# Created by MC2 : Version 2012.02.00.d on 2025/04/08, 10:16:32

###############################################################################
#        Software       : TSMC MEMORY COMPILER 2012.02.00.d
#        Technology     : 28 nm CMOS LOGIC High Performance Compact Mobile Computing Plus 1P10M HKMG CU_ELK 0.9V
#        Memory Type    : TSMC 28nm High Performance Compact Mobile Computing Plus Two Port Register File
#                       : with d240 bit cell HVT periphery
#        Library Name   : ts6n28hpcphvta64x8m4fwbso
#        Library Version: 200b
#        Generated Time : 2025/04/08, 10:16:27
###############################################################################
#
#STATEMENT OF USE
#
#This information contains confidential and proprietary information of TSMC.
#No part of this information may be reproduced, transmitted, transcribed,
#stored in a retrieval system, or translated into any human or computer
#language, in any form or by any means, electronic, mechanical, magnetic,
#optical, chemical, manual, or otherwise, without the prior written permission
#of TSMC. This information was prepared for informational purpose and is for
#use by TSMC's customers only. TSMC reserves the right to make changes in the
#information at any time and without notice.
#
###############################################################################
VERSION 5.7 ;
BUSBITCHARS "[]" ;
DIVIDERCHAR "/" ;

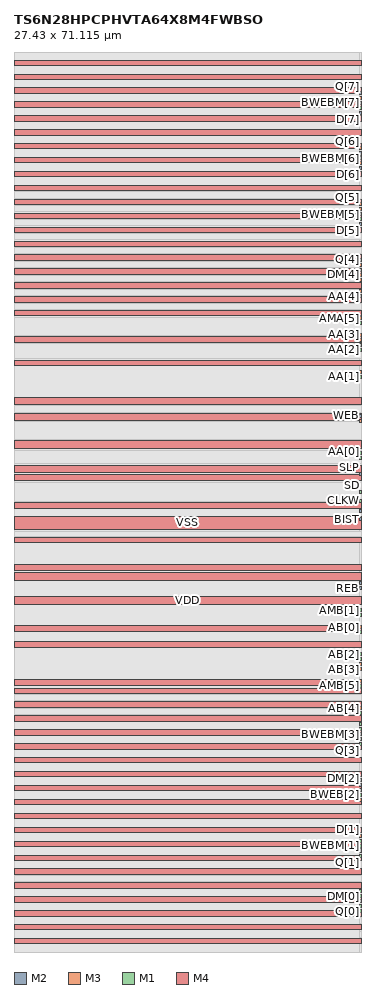
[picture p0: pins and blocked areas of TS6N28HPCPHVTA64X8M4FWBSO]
MACRO TS6N28HPCPHVTA64X8M4FWBSO
	CLASS BLOCK ;
	FOREIGN TS6N28HPCPHVTA64X8M4FWBSO 0.0 0.0 ;
	ORIGIN 0.0 0.0 ;
	SIZE 27.430 BY 71.115 ;
	SYMMETRY X Y ;
	PIN AA[0]
		DIRECTION INPUT ;
		USE SIGNAL ;
		PORT
			LAYER M2 ;
			RECT 27.280 38.930 27.430 39.170 ;
			LAYER M3 ;
			RECT 27.280 38.930 27.430 39.170 ;
			LAYER M1 ;
			RECT 27.280 38.930 27.430 39.170 ;
		END
		ANTENNAGATEAREA 0.0675 LAYER M1 ;
		ANTENNADIFFAREA 0.0360 LAYER M1 ;
		ANTENNAPARTIALMETALAREA 0.6083 LAYER M1 ;
		ANTENNAMAXAREACAR 1.9820 LAYER M1 ;
		ANTENNAPARTIALCUTAREA 0.0345 LAYER VIA1 ;
		ANTENNAMAXAREACAR 0.5856 LAYER VIA1 ;
		ANTENNAGATEAREA 0.0675 LAYER M2 ;
		ANTENNADIFFAREA 0.0360 LAYER M2 ;
		ANTENNAPARTIALMETALAREA 0.7719 LAYER M2 ;
		ANTENNAMAXAREACAR 16.5354 LAYER M2 ;
		ANTENNAPARTIALCUTAREA 0.0165 LAYER VIA2 ;
		ANTENNAMAXAREACAR 0.8398 LAYER VIA2 ;
		ANTENNAGATEAREA 0.0675 LAYER M3 ;
		ANTENNADIFFAREA 0.0360 LAYER M3 ;
		ANTENNAPARTIALMETALAREA 0.7208 LAYER M3 ;
		ANTENNAMAXAREACAR 23.7892 LAYER M3 ;
	END AA[0]

	PIN AA[1]
		DIRECTION INPUT ;
		USE SIGNAL ;
		PORT
			LAYER M3 ;
			RECT 27.280 45.320 27.430 45.560 ;
			LAYER M2 ;
			RECT 27.280 45.320 27.430 45.560 ;
			LAYER M1 ;
			RECT 27.280 45.320 27.430 45.560 ;
		END
		ANTENNAGATEAREA 0.0675 LAYER M1 ;
		ANTENNADIFFAREA 0.0360 LAYER M1 ;
		ANTENNAPARTIALMETALAREA 0.6083 LAYER M1 ;
		ANTENNAMAXAREACAR 1.9820 LAYER M1 ;
		ANTENNAPARTIALCUTAREA 0.0345 LAYER VIA1 ;
		ANTENNAMAXAREACAR 0.5856 LAYER VIA1 ;
		ANTENNAGATEAREA 0.0675 LAYER M2 ;
		ANTENNADIFFAREA 0.0360 LAYER M2 ;
		ANTENNAPARTIALMETALAREA 0.7719 LAYER M2 ;
		ANTENNAMAXAREACAR 16.5354 LAYER M2 ;
		ANTENNAPARTIALCUTAREA 0.0165 LAYER VIA2 ;
		ANTENNAMAXAREACAR 0.8398 LAYER VIA2 ;
		ANTENNAGATEAREA 0.0675 LAYER M3 ;
		ANTENNADIFFAREA 0.0360 LAYER M3 ;
		ANTENNAPARTIALMETALAREA 0.7208 LAYER M3 ;
		ANTENNAMAXAREACAR 23.7892 LAYER M3 ;
	END AA[1]

	PIN AA[2]
		DIRECTION INPUT ;
		USE SIGNAL ;
		PORT
			LAYER M3 ;
			RECT 27.280 47.450 27.430 47.690 ;
			LAYER M2 ;
			RECT 27.280 47.450 27.430 47.690 ;
			LAYER M1 ;
			RECT 27.280 47.450 27.430 47.690 ;
		END
		ANTENNAGATEAREA 0.0675 LAYER M1 ;
		ANTENNADIFFAREA 0.0360 LAYER M1 ;
		ANTENNAPARTIALMETALAREA 0.6083 LAYER M1 ;
		ANTENNAMAXAREACAR 1.9820 LAYER M1 ;
		ANTENNAPARTIALCUTAREA 0.0345 LAYER VIA1 ;
		ANTENNAMAXAREACAR 0.5856 LAYER VIA1 ;
		ANTENNAGATEAREA 0.0675 LAYER M2 ;
		ANTENNADIFFAREA 0.0360 LAYER M2 ;
		ANTENNAPARTIALMETALAREA 0.7719 LAYER M2 ;
		ANTENNAMAXAREACAR 16.5354 LAYER M2 ;
		ANTENNAPARTIALCUTAREA 0.0165 LAYER VIA2 ;
		ANTENNAMAXAREACAR 0.8398 LAYER VIA2 ;
		ANTENNAGATEAREA 0.0675 LAYER M3 ;
		ANTENNADIFFAREA 0.0360 LAYER M3 ;
		ANTENNAPARTIALMETALAREA 0.7208 LAYER M3 ;
		ANTENNAMAXAREACAR 23.7892 LAYER M3 ;
	END AA[2]

	PIN AA[3]
		DIRECTION INPUT ;
		USE SIGNAL ;
		PORT
			LAYER M2 ;
			RECT 27.280 48.645 27.430 48.885 ;
			LAYER M1 ;
			RECT 27.280 48.645 27.430 48.885 ;
			LAYER M3 ;
			RECT 27.280 48.645 27.430 48.885 ;
		END
		ANTENNAGATEAREA 0.0675 LAYER M1 ;
		ANTENNADIFFAREA 0.0360 LAYER M1 ;
		ANTENNAPARTIALMETALAREA 0.6083 LAYER M1 ;
		ANTENNAMAXAREACAR 1.9820 LAYER M1 ;
		ANTENNAPARTIALCUTAREA 0.0345 LAYER VIA1 ;
		ANTENNAMAXAREACAR 0.5856 LAYER VIA1 ;
		ANTENNAGATEAREA 0.0675 LAYER M2 ;
		ANTENNADIFFAREA 0.0360 LAYER M2 ;
		ANTENNAPARTIALMETALAREA 0.7719 LAYER M2 ;
		ANTENNAMAXAREACAR 16.5354 LAYER M2 ;
		ANTENNAPARTIALCUTAREA 0.0165 LAYER VIA2 ;
		ANTENNAMAXAREACAR 0.8398 LAYER VIA2 ;
		ANTENNAGATEAREA 0.0675 LAYER M3 ;
		ANTENNADIFFAREA 0.0360 LAYER M3 ;
		ANTENNAPARTIALMETALAREA 0.7208 LAYER M3 ;
		ANTENNAMAXAREACAR 23.7892 LAYER M3 ;
	END AA[3]

	PIN AA[4]
		DIRECTION INPUT ;
		USE SIGNAL ;
		PORT
			LAYER M1 ;
			RECT 27.280 51.710 27.430 51.950 ;
			LAYER M3 ;
			RECT 27.280 51.710 27.430 51.950 ;
			LAYER M2 ;
			RECT 27.280 51.710 27.430 51.950 ;
		END
		ANTENNAGATEAREA 0.0675 LAYER M1 ;
		ANTENNADIFFAREA 0.0360 LAYER M1 ;
		ANTENNAPARTIALMETALAREA 0.6083 LAYER M1 ;
		ANTENNAMAXAREACAR 1.9820 LAYER M1 ;
		ANTENNAPARTIALCUTAREA 0.0345 LAYER VIA1 ;
		ANTENNAMAXAREACAR 0.5856 LAYER VIA1 ;
		ANTENNAGATEAREA 0.0675 LAYER M2 ;
		ANTENNADIFFAREA 0.0360 LAYER M2 ;
		ANTENNAPARTIALMETALAREA 0.7719 LAYER M2 ;
		ANTENNAMAXAREACAR 16.5354 LAYER M2 ;
		ANTENNAPARTIALCUTAREA 0.0165 LAYER VIA2 ;
		ANTENNAMAXAREACAR 0.8398 LAYER VIA2 ;
		ANTENNAGATEAREA 0.0675 LAYER M3 ;
		ANTENNADIFFAREA 0.0360 LAYER M3 ;
		ANTENNAPARTIALMETALAREA 0.7208 LAYER M3 ;
		ANTENNAMAXAREACAR 23.7892 LAYER M3 ;
	END AA[4]

	PIN AA[5]
		DIRECTION INPUT ;
		USE SIGNAL ;
		PORT
			LAYER M3 ;
			RECT 27.280 49.580 27.430 49.820 ;
			LAYER M2 ;
			RECT 27.280 49.580 27.430 49.820 ;
			LAYER M1 ;
			RECT 27.280 49.580 27.430 49.820 ;
		END
		ANTENNAGATEAREA 0.0675 LAYER M1 ;
		ANTENNADIFFAREA 0.0360 LAYER M1 ;
		ANTENNAPARTIALMETALAREA 0.6083 LAYER M1 ;
		ANTENNAMAXAREACAR 1.9820 LAYER M1 ;
		ANTENNAPARTIALCUTAREA 0.0345 LAYER VIA1 ;
		ANTENNAMAXAREACAR 0.5856 LAYER VIA1 ;
		ANTENNAGATEAREA 0.0675 LAYER M2 ;
		ANTENNADIFFAREA 0.0360 LAYER M2 ;
		ANTENNAPARTIALMETALAREA 0.7719 LAYER M2 ;
		ANTENNAMAXAREACAR 16.5354 LAYER M2 ;
		ANTENNAPARTIALCUTAREA 0.0165 LAYER VIA2 ;
		ANTENNAMAXAREACAR 0.8398 LAYER VIA2 ;
		ANTENNAGATEAREA 0.0675 LAYER M3 ;
		ANTENNADIFFAREA 0.0360 LAYER M3 ;
		ANTENNAPARTIALMETALAREA 0.7208 LAYER M3 ;
		ANTENNAMAXAREACAR 23.7892 LAYER M3 ;
	END AA[5]

	PIN AB[0]
		DIRECTION INPUT ;
		USE SIGNAL ;
		PORT
			LAYER M1 ;
			RECT 27.280 25.550 27.430 25.790 ;
			LAYER M2 ;
			RECT 27.280 25.550 27.430 25.790 ;
			LAYER M3 ;
			RECT 27.280 25.550 27.430 25.790 ;
		END
		ANTENNAGATEAREA 0.0675 LAYER M1 ;
		ANTENNADIFFAREA 0.0360 LAYER M1 ;
		ANTENNAPARTIALMETALAREA 0.7160 LAYER M1 ;
		ANTENNAMAXAREACAR 1.9820 LAYER M1 ;
		ANTENNAPARTIALCUTAREA 0.0360 LAYER VIA1 ;
		ANTENNAMAXAREACAR 0.5856 LAYER VIA1 ;
		ANTENNAGATEAREA 0.0675 LAYER M2 ;
		ANTENNADIFFAREA 0.0360 LAYER M2 ;
		ANTENNAPARTIALMETALAREA 0.8148 LAYER M2 ;
		ANTENNAMAXAREACAR 16.9008 LAYER M2 ;
		ANTENNAPARTIALCUTAREA 0.0165 LAYER VIA2 ;
		ANTENNAMAXAREACAR 0.8398 LAYER VIA2 ;
		ANTENNAGATEAREA 0.0675 LAYER M3 ;
		ANTENNADIFFAREA 0.0360 LAYER M3 ;
		ANTENNAPARTIALMETALAREA 0.7203 LAYER M3 ;
		ANTENNAMAXAREACAR 23.7072 LAYER M3 ;
	END AB[0]

	PIN AB[1]
		DIRECTION INPUT ;
		USE SIGNAL ;
		PORT
			LAYER M3 ;
			RECT 27.280 26.490 27.430 26.730 ;
			LAYER M2 ;
			RECT 27.280 26.490 27.430 26.730 ;
			LAYER M1 ;
			RECT 27.280 26.490 27.430 26.730 ;
		END
		ANTENNAGATEAREA 0.0675 LAYER M1 ;
		ANTENNADIFFAREA 0.0360 LAYER M1 ;
		ANTENNAPARTIALMETALAREA 0.7160 LAYER M1 ;
		ANTENNAMAXAREACAR 1.9820 LAYER M1 ;
		ANTENNAPARTIALCUTAREA 0.0360 LAYER VIA1 ;
		ANTENNAMAXAREACAR 0.5856 LAYER VIA1 ;
		ANTENNAGATEAREA 0.0675 LAYER M2 ;
		ANTENNADIFFAREA 0.0360 LAYER M2 ;
		ANTENNAPARTIALMETALAREA 0.8148 LAYER M2 ;
		ANTENNAMAXAREACAR 16.9008 LAYER M2 ;
		ANTENNAPARTIALCUTAREA 0.0165 LAYER VIA2 ;
		ANTENNAMAXAREACAR 0.8398 LAYER VIA2 ;
		ANTENNAGATEAREA 0.0675 LAYER M3 ;
		ANTENNADIFFAREA 0.0360 LAYER M3 ;
		ANTENNAPARTIALMETALAREA 0.7203 LAYER M3 ;
		ANTENNAMAXAREACAR 23.7072 LAYER M3 ;
	END AB[1]

	PIN AB[2]
		DIRECTION INPUT ;
		USE SIGNAL ;
		PORT
			LAYER M2 ;
			RECT 27.280 23.420 27.430 23.660 ;
			LAYER M3 ;
			RECT 27.280 23.420 27.430 23.660 ;
			LAYER M1 ;
			RECT 27.280 23.420 27.430 23.660 ;
		END
		ANTENNAGATEAREA 0.0675 LAYER M1 ;
		ANTENNADIFFAREA 0.0360 LAYER M1 ;
		ANTENNAPARTIALMETALAREA 0.7160 LAYER M1 ;
		ANTENNAMAXAREACAR 1.9820 LAYER M1 ;
		ANTENNAPARTIALCUTAREA 0.0360 LAYER VIA1 ;
		ANTENNAMAXAREACAR 0.5856 LAYER VIA1 ;
		ANTENNAGATEAREA 0.0675 LAYER M2 ;
		ANTENNADIFFAREA 0.0360 LAYER M2 ;
		ANTENNAPARTIALMETALAREA 0.8148 LAYER M2 ;
		ANTENNAMAXAREACAR 16.9008 LAYER M2 ;
		ANTENNAPARTIALCUTAREA 0.0165 LAYER VIA2 ;
		ANTENNAMAXAREACAR 0.8398 LAYER VIA2 ;
		ANTENNAGATEAREA 0.0675 LAYER M3 ;
		ANTENNADIFFAREA 0.0360 LAYER M3 ;
		ANTENNAPARTIALMETALAREA 0.7203 LAYER M3 ;
		ANTENNAMAXAREACAR 23.7072 LAYER M3 ;
	END AB[2]

	PIN AB[3]
		DIRECTION INPUT ;
		USE SIGNAL ;
		PORT
			LAYER M2 ;
			RECT 27.280 22.230 27.430 22.470 ;
			LAYER M1 ;
			RECT 27.280 22.230 27.430 22.470 ;
			LAYER M3 ;
			RECT 27.280 22.230 27.430 22.470 ;
		END
		ANTENNAGATEAREA 0.0675 LAYER M1 ;
		ANTENNADIFFAREA 0.0360 LAYER M1 ;
		ANTENNAPARTIALMETALAREA 0.7160 LAYER M1 ;
		ANTENNAMAXAREACAR 1.9820 LAYER M1 ;
		ANTENNAPARTIALCUTAREA 0.0360 LAYER VIA1 ;
		ANTENNAMAXAREACAR 0.5856 LAYER VIA1 ;
		ANTENNAGATEAREA 0.0675 LAYER M2 ;
		ANTENNADIFFAREA 0.0360 LAYER M2 ;
		ANTENNAPARTIALMETALAREA 0.8148 LAYER M2 ;
		ANTENNAMAXAREACAR 16.9008 LAYER M2 ;
		ANTENNAPARTIALCUTAREA 0.0165 LAYER VIA2 ;
		ANTENNAMAXAREACAR 0.8398 LAYER VIA2 ;
		ANTENNAGATEAREA 0.0675 LAYER M3 ;
		ANTENNADIFFAREA 0.0360 LAYER M3 ;
		ANTENNAPARTIALMETALAREA 0.7203 LAYER M3 ;
		ANTENNAMAXAREACAR 23.7072 LAYER M3 ;
	END AB[3]

	PIN AB[4]
		DIRECTION INPUT ;
		USE SIGNAL ;
		PORT
			LAYER M1 ;
			RECT 27.280 19.160 27.430 19.400 ;
			LAYER M2 ;
			RECT 27.280 19.160 27.430 19.400 ;
			LAYER M3 ;
			RECT 27.280 19.160 27.430 19.400 ;
		END
		ANTENNAGATEAREA 0.0675 LAYER M1 ;
		ANTENNADIFFAREA 0.0360 LAYER M1 ;
		ANTENNAPARTIALMETALAREA 0.7160 LAYER M1 ;
		ANTENNAMAXAREACAR 1.9820 LAYER M1 ;
		ANTENNAPARTIALCUTAREA 0.0360 LAYER VIA1 ;
		ANTENNAMAXAREACAR 0.5856 LAYER VIA1 ;
		ANTENNAGATEAREA 0.0675 LAYER M2 ;
		ANTENNADIFFAREA 0.0360 LAYER M2 ;
		ANTENNAPARTIALMETALAREA 0.8148 LAYER M2 ;
		ANTENNAMAXAREACAR 16.9008 LAYER M2 ;
		ANTENNAPARTIALCUTAREA 0.0165 LAYER VIA2 ;
		ANTENNAMAXAREACAR 0.8398 LAYER VIA2 ;
		ANTENNAGATEAREA 0.0675 LAYER M3 ;
		ANTENNADIFFAREA 0.0360 LAYER M3 ;
		ANTENNAPARTIALMETALAREA 0.7203 LAYER M3 ;
		ANTENNAMAXAREACAR 23.7072 LAYER M3 ;
	END AB[4]

	PIN AB[5]
		DIRECTION INPUT ;
		USE SIGNAL ;
		PORT
			LAYER M2 ;
			RECT 27.280 21.290 27.430 21.530 ;
			LAYER M1 ;
			RECT 27.280 21.290 27.430 21.530 ;
			LAYER M3 ;
			RECT 27.280 21.290 27.430 21.530 ;
		END
		ANTENNAGATEAREA 0.0675 LAYER M1 ;
		ANTENNADIFFAREA 0.0360 LAYER M1 ;
		ANTENNAPARTIALMETALAREA 0.7160 LAYER M1 ;
		ANTENNAMAXAREACAR 1.9820 LAYER M1 ;
		ANTENNAPARTIALCUTAREA 0.0360 LAYER VIA1 ;
		ANTENNAMAXAREACAR 0.5856 LAYER VIA1 ;
		ANTENNAGATEAREA 0.0675 LAYER M2 ;
		ANTENNADIFFAREA 0.0360 LAYER M2 ;
		ANTENNAPARTIALMETALAREA 0.8148 LAYER M2 ;
		ANTENNAMAXAREACAR 16.9008 LAYER M2 ;
		ANTENNAPARTIALCUTAREA 0.0165 LAYER VIA2 ;
		ANTENNAMAXAREACAR 0.8398 LAYER VIA2 ;
		ANTENNAGATEAREA 0.0675 LAYER M3 ;
		ANTENNADIFFAREA 0.0360 LAYER M3 ;
		ANTENNAPARTIALMETALAREA 0.7203 LAYER M3 ;
		ANTENNAMAXAREACAR 23.7072 LAYER M3 ;
	END AB[5]

	PIN AMA[0]
		DIRECTION INPUT ;
		USE SIGNAL ;
		PORT
			LAYER M2 ;
			RECT 27.280 39.315 27.430 39.555 ;
			LAYER M3 ;
			RECT 27.280 39.315 27.430 39.555 ;
			LAYER M1 ;
			RECT 27.280 39.315 27.430 39.555 ;
		END
		ANTENNAGATEAREA 0.0196 LAYER M1 ;
		ANTENNADIFFAREA 0.0360 LAYER M1 ;
		ANTENNAPARTIALMETALAREA 0.0945 LAYER M1 ;
		ANTENNAMAXAREACAR 0.8036 LAYER M1 ;
		ANTENNAPARTIALCUTAREA 0.0115 LAYER VIA1 ;
		ANTENNAMAXAREACAR 0.1276 LAYER VIA1 ;
		ANTENNAGATEAREA 0.0196 LAYER M2 ;
		ANTENNADIFFAREA 0.0360 LAYER M2 ;
		ANTENNAPARTIALMETALAREA 0.0816 LAYER M2 ;
		ANTENNAMAXAREACAR 4.9668 LAYER M2 ;
		ANTENNAPARTIALCUTAREA 0.0065 LAYER VIA2 ;
		ANTENNAMAXAREACAR 0.4592 LAYER VIA2 ;
		ANTENNAGATEAREA 0.0196 LAYER M3 ;
		ANTENNADIFFAREA 0.0360 LAYER M3 ;
		ANTENNAPARTIALMETALAREA 0.0360 LAYER M3 ;
		ANTENNAMAXAREACAR 6.8036 LAYER M3 ;
	END AMA[0]

	PIN AMA[1]
		DIRECTION INPUT ;
		USE SIGNAL ;
		PORT
			LAYER M1 ;
			RECT 27.280 45.705 27.430 45.945 ;
			LAYER M2 ;
			RECT 27.280 45.705 27.430 45.945 ;
			LAYER M3 ;
			RECT 27.280 45.705 27.430 45.945 ;
		END
		ANTENNAGATEAREA 0.0196 LAYER M1 ;
		ANTENNADIFFAREA 0.0360 LAYER M1 ;
		ANTENNAPARTIALMETALAREA 0.0945 LAYER M1 ;
		ANTENNAMAXAREACAR 0.8036 LAYER M1 ;
		ANTENNAPARTIALCUTAREA 0.0115 LAYER VIA1 ;
		ANTENNAMAXAREACAR 0.1276 LAYER VIA1 ;
		ANTENNAGATEAREA 0.0196 LAYER M2 ;
		ANTENNADIFFAREA 0.0360 LAYER M2 ;
		ANTENNAPARTIALMETALAREA 0.0816 LAYER M2 ;
		ANTENNAMAXAREACAR 4.9668 LAYER M2 ;
		ANTENNAPARTIALCUTAREA 0.0065 LAYER VIA2 ;
		ANTENNAMAXAREACAR 0.4592 LAYER VIA2 ;
		ANTENNAGATEAREA 0.0196 LAYER M3 ;
		ANTENNADIFFAREA 0.0360 LAYER M3 ;
		ANTENNAPARTIALMETALAREA 0.0360 LAYER M3 ;
		ANTENNAMAXAREACAR 6.8036 LAYER M3 ;
	END AMA[1]

	PIN AMA[2]
		DIRECTION INPUT ;
		USE SIGNAL ;
		PORT
			LAYER M3 ;
			RECT 27.280 47.865 27.430 48.105 ;
			LAYER M1 ;
			RECT 27.280 47.865 27.430 48.105 ;
			LAYER M2 ;
			RECT 27.280 47.865 27.430 48.105 ;
		END
		ANTENNAGATEAREA 0.0196 LAYER M1 ;
		ANTENNADIFFAREA 0.0360 LAYER M1 ;
		ANTENNAPARTIALMETALAREA 0.0945 LAYER M1 ;
		ANTENNAMAXAREACAR 0.8036 LAYER M1 ;
		ANTENNAPARTIALCUTAREA 0.0115 LAYER VIA1 ;
		ANTENNAMAXAREACAR 0.1276 LAYER VIA1 ;
		ANTENNAGATEAREA 0.0196 LAYER M2 ;
		ANTENNADIFFAREA 0.0360 LAYER M2 ;
		ANTENNAPARTIALMETALAREA 0.0816 LAYER M2 ;
		ANTENNAMAXAREACAR 4.9668 LAYER M2 ;
		ANTENNAPARTIALCUTAREA 0.0065 LAYER VIA2 ;
		ANTENNAMAXAREACAR 0.4592 LAYER VIA2 ;
		ANTENNAGATEAREA 0.0196 LAYER M3 ;
		ANTENNADIFFAREA 0.0360 LAYER M3 ;
		ANTENNAPARTIALMETALAREA 0.0360 LAYER M3 ;
		ANTENNAMAXAREACAR 6.8036 LAYER M3 ;
	END AMA[2]

	PIN AMA[3]
		DIRECTION INPUT ;
		USE SIGNAL ;
		PORT
			LAYER M2 ;
			RECT 27.280 48.255 27.430 48.495 ;
			LAYER M1 ;
			RECT 27.280 48.255 27.430 48.495 ;
			LAYER M3 ;
			RECT 27.280 48.255 27.430 48.495 ;
		END
		ANTENNAGATEAREA 0.0196 LAYER M1 ;
		ANTENNADIFFAREA 0.0360 LAYER M1 ;
		ANTENNAPARTIALMETALAREA 0.0945 LAYER M1 ;
		ANTENNAMAXAREACAR 0.8036 LAYER M1 ;
		ANTENNAPARTIALCUTAREA 0.0115 LAYER VIA1 ;
		ANTENNAMAXAREACAR 0.1276 LAYER VIA1 ;
		ANTENNAGATEAREA 0.0196 LAYER M2 ;
		ANTENNADIFFAREA 0.0360 LAYER M2 ;
		ANTENNAPARTIALMETALAREA 0.0816 LAYER M2 ;
		ANTENNAMAXAREACAR 4.9668 LAYER M2 ;
		ANTENNAPARTIALCUTAREA 0.0065 LAYER VIA2 ;
		ANTENNAMAXAREACAR 0.4592 LAYER VIA2 ;
		ANTENNAGATEAREA 0.0196 LAYER M3 ;
		ANTENNADIFFAREA 0.0360 LAYER M3 ;
		ANTENNAPARTIALMETALAREA 0.0360 LAYER M3 ;
		ANTENNAMAXAREACAR 6.8036 LAYER M3 ;
	END AMA[3]

	PIN AMA[4]
		DIRECTION INPUT ;
		USE SIGNAL ;
		PORT
			LAYER M2 ;
			RECT 27.280 52.125 27.430 52.365 ;
			LAYER M1 ;
			RECT 27.280 52.125 27.430 52.365 ;
			LAYER M3 ;
			RECT 27.280 52.125 27.430 52.365 ;
		END
		ANTENNAGATEAREA 0.0196 LAYER M1 ;
		ANTENNADIFFAREA 0.0360 LAYER M1 ;
		ANTENNAPARTIALMETALAREA 0.0945 LAYER M1 ;
		ANTENNAMAXAREACAR 0.8036 LAYER M1 ;
		ANTENNAPARTIALCUTAREA 0.0115 LAYER VIA1 ;
		ANTENNAMAXAREACAR 0.1276 LAYER VIA1 ;
		ANTENNAGATEAREA 0.0196 LAYER M2 ;
		ANTENNADIFFAREA 0.0360 LAYER M2 ;
		ANTENNAPARTIALMETALAREA 0.0816 LAYER M2 ;
		ANTENNAMAXAREACAR 4.9668 LAYER M2 ;
		ANTENNAPARTIALCUTAREA 0.0065 LAYER VIA2 ;
		ANTENNAMAXAREACAR 0.4592 LAYER VIA2 ;
		ANTENNAGATEAREA 0.0196 LAYER M3 ;
		ANTENNADIFFAREA 0.0360 LAYER M3 ;
		ANTENNAPARTIALMETALAREA 0.0360 LAYER M3 ;
		ANTENNAMAXAREACAR 6.8036 LAYER M3 ;
	END AMA[4]

	PIN AMA[5]
		DIRECTION INPUT ;
		USE SIGNAL ;
		PORT
			LAYER M2 ;
			RECT 27.280 49.965 27.430 50.205 ;
			LAYER M1 ;
			RECT 27.280 49.965 27.430 50.205 ;
			LAYER M3 ;
			RECT 27.280 49.965 27.430 50.205 ;
		END
		ANTENNAGATEAREA 0.0196 LAYER M1 ;
		ANTENNADIFFAREA 0.0360 LAYER M1 ;
		ANTENNAPARTIALMETALAREA 0.0945 LAYER M1 ;
		ANTENNAMAXAREACAR 0.8036 LAYER M1 ;
		ANTENNAPARTIALCUTAREA 0.0115 LAYER VIA1 ;
		ANTENNAMAXAREACAR 0.1276 LAYER VIA1 ;
		ANTENNAGATEAREA 0.0196 LAYER M2 ;
		ANTENNADIFFAREA 0.0360 LAYER M2 ;
		ANTENNAPARTIALMETALAREA 0.0816 LAYER M2 ;
		ANTENNAMAXAREACAR 4.9668 LAYER M2 ;
		ANTENNAPARTIALCUTAREA 0.0065 LAYER VIA2 ;
		ANTENNAMAXAREACAR 0.4592 LAYER VIA2 ;
		ANTENNAGATEAREA 0.0196 LAYER M3 ;
		ANTENNADIFFAREA 0.0360 LAYER M3 ;
		ANTENNAPARTIALMETALAREA 0.0360 LAYER M3 ;
		ANTENNAMAXAREACAR 6.8036 LAYER M3 ;
	END AMA[5]

	PIN AMB[0]
		DIRECTION INPUT ;
		USE SIGNAL ;
		PORT
			LAYER M3 ;
			RECT 27.280 25.160 27.430 25.400 ;
			LAYER M2 ;
			RECT 27.280 25.160 27.430 25.400 ;
			LAYER M1 ;
			RECT 27.280 25.160 27.430 25.400 ;
		END
		ANTENNAGATEAREA 0.0196 LAYER M1 ;
		ANTENNADIFFAREA 0.0360 LAYER M1 ;
		ANTENNAPARTIALMETALAREA 0.0945 LAYER M1 ;
		ANTENNAMAXAREACAR 0.8036 LAYER M1 ;
		ANTENNAPARTIALCUTAREA 0.0115 LAYER VIA1 ;
		ANTENNAMAXAREACAR 0.1276 LAYER VIA1 ;
		ANTENNAGATEAREA 0.0196 LAYER M2 ;
		ANTENNADIFFAREA 0.0360 LAYER M2 ;
		ANTENNAPARTIALMETALAREA 0.0816 LAYER M2 ;
		ANTENNAMAXAREACAR 4.9668 LAYER M2 ;
		ANTENNAPARTIALCUTAREA 0.0065 LAYER VIA2 ;
		ANTENNAMAXAREACAR 0.4592 LAYER VIA2 ;
		ANTENNAGATEAREA 0.0196 LAYER M3 ;
		ANTENNADIFFAREA 0.0360 LAYER M3 ;
		ANTENNAPARTIALMETALAREA 0.0360 LAYER M3 ;
		ANTENNAMAXAREACAR 6.8036 LAYER M3 ;
	END AMB[0]

	PIN AMB[1]
		DIRECTION INPUT ;
		USE SIGNAL ;
		PORT
			LAYER M3 ;
			RECT 27.280 26.875 27.430 27.115 ;
			LAYER M2 ;
			RECT 27.280 26.875 27.430 27.115 ;
			LAYER M1 ;
			RECT 27.280 26.875 27.430 27.115 ;
		END
		ANTENNAGATEAREA 0.0196 LAYER M1 ;
		ANTENNADIFFAREA 0.0360 LAYER M1 ;
		ANTENNAPARTIALMETALAREA 0.0945 LAYER M1 ;
		ANTENNAMAXAREACAR 0.8036 LAYER M1 ;
		ANTENNAPARTIALCUTAREA 0.0115 LAYER VIA1 ;
		ANTENNAMAXAREACAR 0.1276 LAYER VIA1 ;
		ANTENNAGATEAREA 0.0196 LAYER M2 ;
		ANTENNADIFFAREA 0.0360 LAYER M2 ;
		ANTENNAPARTIALMETALAREA 0.0816 LAYER M2 ;
		ANTENNAMAXAREACAR 4.9668 LAYER M2 ;
		ANTENNAPARTIALCUTAREA 0.0065 LAYER VIA2 ;
		ANTENNAMAXAREACAR 0.4592 LAYER VIA2 ;
		ANTENNAGATEAREA 0.0196 LAYER M3 ;
		ANTENNADIFFAREA 0.0360 LAYER M3 ;
		ANTENNAPARTIALMETALAREA 0.0360 LAYER M3 ;
		ANTENNAMAXAREACAR 6.8036 LAYER M3 ;
	END AMB[1]

	PIN AMB[2]
		DIRECTION INPUT ;
		USE SIGNAL ;
		PORT
			LAYER M3 ;
			RECT 27.280 23.030 27.430 23.270 ;
			LAYER M2 ;
			RECT 27.280 23.030 27.430 23.270 ;
			LAYER M1 ;
			RECT 27.280 23.030 27.430 23.270 ;
		END
		ANTENNAGATEAREA 0.0196 LAYER M1 ;
		ANTENNADIFFAREA 0.0360 LAYER M1 ;
		ANTENNAPARTIALMETALAREA 0.0945 LAYER M1 ;
		ANTENNAMAXAREACAR 0.8036 LAYER M1 ;
		ANTENNAPARTIALCUTAREA 0.0115 LAYER VIA1 ;
		ANTENNAMAXAREACAR 0.1276 LAYER VIA1 ;
		ANTENNAGATEAREA 0.0196 LAYER M2 ;
		ANTENNADIFFAREA 0.0360 LAYER M2 ;
		ANTENNAPARTIALMETALAREA 0.0816 LAYER M2 ;
		ANTENNAMAXAREACAR 4.9668 LAYER M2 ;
		ANTENNAPARTIALCUTAREA 0.0065 LAYER VIA2 ;
		ANTENNAMAXAREACAR 0.4592 LAYER VIA2 ;
		ANTENNAGATEAREA 0.0196 LAYER M3 ;
		ANTENNADIFFAREA 0.0360 LAYER M3 ;
		ANTENNAPARTIALMETALAREA 0.0360 LAYER M3 ;
		ANTENNAMAXAREACAR 6.8036 LAYER M3 ;
	END AMB[2]

	PIN AMB[3]
		DIRECTION INPUT ;
		USE SIGNAL ;
		PORT
			LAYER M1 ;
			RECT 27.280 22.645 27.430 22.885 ;
			LAYER M2 ;
			RECT 27.280 22.645 27.430 22.885 ;
			LAYER M3 ;
			RECT 27.280 22.645 27.430 22.885 ;
		END
		ANTENNAGATEAREA 0.0196 LAYER M1 ;
		ANTENNADIFFAREA 0.0360 LAYER M1 ;
		ANTENNAPARTIALMETALAREA 0.0945 LAYER M1 ;
		ANTENNAMAXAREACAR 0.8036 LAYER M1 ;
		ANTENNAPARTIALCUTAREA 0.0115 LAYER VIA1 ;
		ANTENNAMAXAREACAR 0.1276 LAYER VIA1 ;
		ANTENNAGATEAREA 0.0196 LAYER M2 ;
		ANTENNADIFFAREA 0.0360 LAYER M2 ;
		ANTENNAPARTIALMETALAREA 0.0816 LAYER M2 ;
		ANTENNAMAXAREACAR 4.9668 LAYER M2 ;
		ANTENNAPARTIALCUTAREA 0.0065 LAYER VIA2 ;
		ANTENNAMAXAREACAR 0.4592 LAYER VIA2 ;
		ANTENNAGATEAREA 0.0196 LAYER M3 ;
		ANTENNADIFFAREA 0.0360 LAYER M3 ;
		ANTENNAPARTIALMETALAREA 0.0360 LAYER M3 ;
		ANTENNAMAXAREACAR 6.8036 LAYER M3 ;
	END AMB[3]

	PIN AMB[4]
		DIRECTION INPUT ;
		USE SIGNAL ;
		PORT
			LAYER M3 ;
			RECT 27.280 18.745 27.430 18.985 ;
			LAYER M2 ;
			RECT 27.280 18.745 27.430 18.985 ;
			LAYER M1 ;
			RECT 27.280 18.745 27.430 18.985 ;
		END
		ANTENNAGATEAREA 0.0196 LAYER M1 ;
		ANTENNADIFFAREA 0.0360 LAYER M1 ;
		ANTENNAPARTIALMETALAREA 0.0945 LAYER M1 ;
		ANTENNAMAXAREACAR 0.8036 LAYER M1 ;
		ANTENNAPARTIALCUTAREA 0.0115 LAYER VIA1 ;
		ANTENNAMAXAREACAR 0.1276 LAYER VIA1 ;
		ANTENNAGATEAREA 0.0196 LAYER M2 ;
		ANTENNADIFFAREA 0.0360 LAYER M2 ;
		ANTENNAPARTIALMETALAREA 0.0816 LAYER M2 ;
		ANTENNAMAXAREACAR 4.9668 LAYER M2 ;
		ANTENNAPARTIALCUTAREA 0.0065 LAYER VIA2 ;
		ANTENNAMAXAREACAR 0.4592 LAYER VIA2 ;
		ANTENNAGATEAREA 0.0196 LAYER M3 ;
		ANTENNADIFFAREA 0.0360 LAYER M3 ;
		ANTENNAPARTIALMETALAREA 0.0360 LAYER M3 ;
		ANTENNAMAXAREACAR 6.8036 LAYER M3 ;
	END AMB[4]

	PIN AMB[5]
		DIRECTION INPUT ;
		USE SIGNAL ;
		PORT
			LAYER M2 ;
			RECT 27.280 20.905 27.430 21.145 ;
			LAYER M3 ;
			RECT 27.280 20.905 27.430 21.145 ;
			LAYER M1 ;
			RECT 27.280 20.905 27.430 21.145 ;
		END
		ANTENNAGATEAREA 0.0196 LAYER M1 ;
		ANTENNADIFFAREA 0.0360 LAYER M1 ;
		ANTENNAPARTIALMETALAREA 0.0945 LAYER M1 ;
		ANTENNAMAXAREACAR 0.8036 LAYER M1 ;
		ANTENNAPARTIALCUTAREA 0.0115 LAYER VIA1 ;
		ANTENNAMAXAREACAR 0.1276 LAYER VIA1 ;
		ANTENNAGATEAREA 0.0196 LAYER M2 ;
		ANTENNADIFFAREA 0.0360 LAYER M2 ;
		ANTENNAPARTIALMETALAREA 0.0816 LAYER M2 ;
		ANTENNAMAXAREACAR 4.9668 LAYER M2 ;
		ANTENNAPARTIALCUTAREA 0.0065 LAYER VIA2 ;
		ANTENNAMAXAREACAR 0.4592 LAYER VIA2 ;
		ANTENNAGATEAREA 0.0196 LAYER M3 ;
		ANTENNADIFFAREA 0.0360 LAYER M3 ;
		ANTENNAPARTIALMETALAREA 0.0360 LAYER M3 ;
		ANTENNAMAXAREACAR 6.8036 LAYER M3 ;
	END AMB[5]

	PIN BIST
		DIRECTION INPUT ;
		USE SIGNAL ;
		PORT
			LAYER M3 ;
			RECT 27.280 34.090 27.430 34.330 ;
			LAYER M1 ;
			RECT 27.280 34.090 27.430 34.330 ;
			LAYER M2 ;
			RECT 27.280 34.090 27.430 34.330 ;
		END
		ANTENNAGATEAREA 0.3500 LAYER M1 ;
		ANTENNADIFFAREA 0.0360 LAYER M1 ;
		ANTENNAPARTIALMETALAREA 0.3368 LAYER M1 ;
		ANTENNAMAXAREACAR 0.7371 LAYER M1 ;
		ANTENNAPARTIALCUTAREA 0.0155 LAYER VIA1 ;
		ANTENNAMAXAREACAR 0.0186 LAYER VIA1 ;
		ANTENNAGATEAREA 0.3500 LAYER M2 ;
		ANTENNADIFFAREA 0.0360 LAYER M2 ;
		ANTENNAPARTIALMETALAREA 0.1411 LAYER M2 ;
		ANTENNAMAXAREACAR 1.1403 LAYER M2 ;
		ANTENNAPARTIALCUTAREA 0.0065 LAYER VIA2 ;
		ANTENNAMAXAREACAR 0.0371 LAYER VIA2 ;
		ANTENNAGATEAREA 0.3500 LAYER M3 ;
		ANTENNADIFFAREA 0.0360 LAYER M3 ;
		ANTENNAPARTIALMETALAREA 0.0360 LAYER M3 ;
		ANTENNAMAXAREACAR 1.2431 LAYER M3 ;
	END BIST

	PIN BWEBM[0]
		DIRECTION INPUT ;
		USE SIGNAL ;
		PORT
			LAYER M1 ;
			RECT 27.280 3.890 27.430 4.130 ;
			LAYER M3 ;
			RECT 27.280 3.890 27.430 4.130 ;
			LAYER M2 ;
			RECT 27.280 3.890 27.430 4.130 ;
		END
		ANTENNAGATEAREA 0.0196 LAYER M1 ;
		ANTENNADIFFAREA 0.0360 LAYER M1 ;
		ANTENNAPARTIALMETALAREA 0.0945 LAYER M1 ;
		ANTENNAMAXAREACAR 0.8036 LAYER M1 ;
		ANTENNAPARTIALCUTAREA 0.0115 LAYER VIA1 ;
		ANTENNAMAXAREACAR 0.1276 LAYER VIA1 ;
		ANTENNAGATEAREA 0.0196 LAYER M2 ;
		ANTENNADIFFAREA 0.0360 LAYER M2 ;
		ANTENNAPARTIALMETALAREA 0.0875 LAYER M2 ;
		ANTENNAMAXAREACAR 5.2679 LAYER M2 ;
		ANTENNAPARTIALCUTAREA 0.0065 LAYER VIA2 ;
		ANTENNAMAXAREACAR 0.4592 LAYER VIA2 ;
		ANTENNAGATEAREA 0.0196 LAYER M3 ;
		ANTENNADIFFAREA 0.0360 LAYER M3 ;
		ANTENNAPARTIALMETALAREA 0.0360 LAYER M3 ;
		ANTENNAMAXAREACAR 7.1046 LAYER M3 ;
	END BWEBM[0]

	PIN BWEBM[1]
		DIRECTION INPUT ;
		USE SIGNAL ;
		PORT
			LAYER M2 ;
			RECT 27.280 8.290 27.430 8.530 ;
			LAYER M3 ;
			RECT 27.280 8.290 27.430 8.530 ;
			LAYER M1 ;
			RECT 27.280 8.290 27.430 8.530 ;
		END
		ANTENNAGATEAREA 0.0196 LAYER M1 ;
		ANTENNADIFFAREA 0.0360 LAYER M1 ;
		ANTENNAPARTIALMETALAREA 0.0945 LAYER M1 ;
		ANTENNAMAXAREACAR 0.8036 LAYER M1 ;
		ANTENNAPARTIALCUTAREA 0.0115 LAYER VIA1 ;
		ANTENNAMAXAREACAR 0.1276 LAYER VIA1 ;
		ANTENNAGATEAREA 0.0196 LAYER M2 ;
		ANTENNADIFFAREA 0.0360 LAYER M2 ;
		ANTENNAPARTIALMETALAREA 0.0875 LAYER M2 ;
		ANTENNAMAXAREACAR 5.2679 LAYER M2 ;
		ANTENNAPARTIALCUTAREA 0.0065 LAYER VIA2 ;
		ANTENNAMAXAREACAR 0.4592 LAYER VIA2 ;
		ANTENNAGATEAREA 0.0196 LAYER M3 ;
		ANTENNADIFFAREA 0.0360 LAYER M3 ;
		ANTENNAPARTIALMETALAREA 0.0360 LAYER M3 ;
		ANTENNAMAXAREACAR 7.1046 LAYER M3 ;
	END BWEBM[1]

	PIN BWEBM[2]
		DIRECTION INPUT ;
		USE SIGNAL ;
		PORT
			LAYER M1 ;
			RECT 27.280 12.690 27.430 12.930 ;
			LAYER M3 ;
			RECT 27.280 12.690 27.430 12.930 ;
			LAYER M2 ;
			RECT 27.280 12.690 27.430 12.930 ;
		END
		ANTENNAGATEAREA 0.0196 LAYER M1 ;
		ANTENNADIFFAREA 0.0360 LAYER M1 ;
		ANTENNAPARTIALMETALAREA 0.0945 LAYER M1 ;
		ANTENNAMAXAREACAR 0.8036 LAYER M1 ;
		ANTENNAPARTIALCUTAREA 0.0115 LAYER VIA1 ;
		ANTENNAMAXAREACAR 0.1276 LAYER VIA1 ;
		ANTENNAGATEAREA 0.0196 LAYER M2 ;
		ANTENNADIFFAREA 0.0360 LAYER M2 ;
		ANTENNAPARTIALMETALAREA 0.0875 LAYER M2 ;
		ANTENNAMAXAREACAR 5.2679 LAYER M2 ;
		ANTENNAPARTIALCUTAREA 0.0065 LAYER VIA2 ;
		ANTENNAMAXAREACAR 0.4592 LAYER VIA2 ;
		ANTENNAGATEAREA 0.0196 LAYER M3 ;
		ANTENNADIFFAREA 0.0360 LAYER M3 ;
		ANTENNAPARTIALMETALAREA 0.0360 LAYER M3 ;
		ANTENNAMAXAREACAR 7.1046 LAYER M3 ;
	END BWEBM[2]

	PIN BWEBM[3]
		DIRECTION INPUT ;
		USE SIGNAL ;
		PORT
			LAYER M1 ;
			RECT 27.280 17.090 27.430 17.330 ;
			LAYER M3 ;
			RECT 27.280 17.090 27.430 17.330 ;
			LAYER M2 ;
			RECT 27.280 17.090 27.430 17.330 ;
		END
		ANTENNAGATEAREA 0.0196 LAYER M1 ;
		ANTENNADIFFAREA 0.0360 LAYER M1 ;
		ANTENNAPARTIALMETALAREA 0.0945 LAYER M1 ;
		ANTENNAMAXAREACAR 0.8036 LAYER M1 ;
		ANTENNAPARTIALCUTAREA 0.0115 LAYER VIA1 ;
		ANTENNAMAXAREACAR 0.1276 LAYER VIA1 ;
		ANTENNAGATEAREA 0.0196 LAYER M2 ;
		ANTENNADIFFAREA 0.0360 LAYER M2 ;
		ANTENNAPARTIALMETALAREA 0.0875 LAYER M2 ;
		ANTENNAMAXAREACAR 5.2679 LAYER M2 ;
		ANTENNAPARTIALCUTAREA 0.0065 LAYER VIA2 ;
		ANTENNAMAXAREACAR 0.4592 LAYER VIA2 ;
		ANTENNAGATEAREA 0.0196 LAYER M3 ;
		ANTENNADIFFAREA 0.0360 LAYER M3 ;
		ANTENNAPARTIALMETALAREA 0.0360 LAYER M3 ;
		ANTENNAMAXAREACAR 7.1046 LAYER M3 ;
	END BWEBM[3]

	PIN BWEBM[4]
		DIRECTION INPUT ;
		USE SIGNAL ;
		PORT
			LAYER M1 ;
			RECT 27.280 53.785 27.430 54.025 ;
			LAYER M3 ;
			RECT 27.280 53.785 27.430 54.025 ;
			LAYER M2 ;
			RECT 27.280 53.785 27.430 54.025 ;
		END
		ANTENNAGATEAREA 0.0196 LAYER M1 ;
		ANTENNADIFFAREA 0.0360 LAYER M1 ;
		ANTENNAPARTIALMETALAREA 0.0945 LAYER M1 ;
		ANTENNAMAXAREACAR 0.8036 LAYER M1 ;
		ANTENNAPARTIALCUTAREA 0.0115 LAYER VIA1 ;
		ANTENNAMAXAREACAR 0.1276 LAYER VIA1 ;
		ANTENNAGATEAREA 0.0196 LAYER M2 ;
		ANTENNADIFFAREA 0.0360 LAYER M2 ;
		ANTENNAPARTIALMETALAREA 0.0875 LAYER M2 ;
		ANTENNAMAXAREACAR 5.2679 LAYER M2 ;
		ANTENNAPARTIALCUTAREA 0.0065 LAYER VIA2 ;
		ANTENNAMAXAREACAR 0.4592 LAYER VIA2 ;
		ANTENNAGATEAREA 0.0196 LAYER M3 ;
		ANTENNADIFFAREA 0.0360 LAYER M3 ;
		ANTENNAPARTIALMETALAREA 0.0360 LAYER M3 ;
		ANTENNAMAXAREACAR 7.1046 LAYER M3 ;
	END BWEBM[4]

	PIN BWEBM[5]
		DIRECTION INPUT ;
		USE SIGNAL ;
		PORT
			LAYER M3 ;
			RECT 27.280 58.185 27.430 58.425 ;
			LAYER M1 ;
			RECT 27.280 58.185 27.430 58.425 ;
			LAYER M2 ;
			RECT 27.280 58.185 27.430 58.425 ;
		END
		ANTENNAGATEAREA 0.0196 LAYER M1 ;
		ANTENNADIFFAREA 0.0360 LAYER M1 ;
		ANTENNAPARTIALMETALAREA 0.0945 LAYER M1 ;
		ANTENNAMAXAREACAR 0.8036 LAYER M1 ;
		ANTENNAPARTIALCUTAREA 0.0115 LAYER VIA1 ;
		ANTENNAMAXAREACAR 0.1276 LAYER VIA1 ;
		ANTENNAGATEAREA 0.0196 LAYER M2 ;
		ANTENNADIFFAREA 0.0360 LAYER M2 ;
		ANTENNAPARTIALMETALAREA 0.0875 LAYER M2 ;
		ANTENNAMAXAREACAR 5.2679 LAYER M2 ;
		ANTENNAPARTIALCUTAREA 0.0065 LAYER VIA2 ;
		ANTENNAMAXAREACAR 0.4592 LAYER VIA2 ;
		ANTENNAGATEAREA 0.0196 LAYER M3 ;
		ANTENNADIFFAREA 0.0360 LAYER M3 ;
		ANTENNAPARTIALMETALAREA 0.0360 LAYER M3 ;
		ANTENNAMAXAREACAR 7.1046 LAYER M3 ;
	END BWEBM[5]

	PIN BWEBM[6]
		DIRECTION INPUT ;
		USE SIGNAL ;
		PORT
			LAYER M3 ;
			RECT 27.280 62.585 27.430 62.825 ;
			LAYER M1 ;
			RECT 27.280 62.585 27.430 62.825 ;
			LAYER M2 ;
			RECT 27.280 62.585 27.430 62.825 ;
		END
		ANTENNAGATEAREA 0.0196 LAYER M1 ;
		ANTENNADIFFAREA 0.0360 LAYER M1 ;
		ANTENNAPARTIALMETALAREA 0.0945 LAYER M1 ;
		ANTENNAMAXAREACAR 0.8036 LAYER M1 ;
		ANTENNAPARTIALCUTAREA 0.0115 LAYER VIA1 ;
		ANTENNAMAXAREACAR 0.1276 LAYER VIA1 ;
		ANTENNAGATEAREA 0.0196 LAYER M2 ;
		ANTENNADIFFAREA 0.0360 LAYER M2 ;
		ANTENNAPARTIALMETALAREA 0.0875 LAYER M2 ;
		ANTENNAMAXAREACAR 5.2679 LAYER M2 ;
		ANTENNAPARTIALCUTAREA 0.0065 LAYER VIA2 ;
		ANTENNAMAXAREACAR 0.4592 LAYER VIA2 ;
		ANTENNAGATEAREA 0.0196 LAYER M3 ;
		ANTENNADIFFAREA 0.0360 LAYER M3 ;
		ANTENNAPARTIALMETALAREA 0.0360 LAYER M3 ;
		ANTENNAMAXAREACAR 7.1046 LAYER M3 ;
	END BWEBM[6]

	PIN BWEBM[7]
		DIRECTION INPUT ;
		USE SIGNAL ;
		PORT
			LAYER M1 ;
			RECT 27.280 66.985 27.430 67.225 ;
			LAYER M3 ;
			RECT 27.280 66.985 27.430 67.225 ;
			LAYER M2 ;
			RECT 27.280 66.985 27.430 67.225 ;
		END
		ANTENNAGATEAREA 0.0196 LAYER M1 ;
		ANTENNADIFFAREA 0.0360 LAYER M1 ;
		ANTENNAPARTIALMETALAREA 0.0945 LAYER M1 ;
		ANTENNAMAXAREACAR 0.8036 LAYER M1 ;
		ANTENNAPARTIALCUTAREA 0.0115 LAYER VIA1 ;
		ANTENNAMAXAREACAR 0.1276 LAYER VIA1 ;
		ANTENNAGATEAREA 0.0196 LAYER M2 ;
		ANTENNADIFFAREA 0.0360 LAYER M2 ;
		ANTENNAPARTIALMETALAREA 0.0875 LAYER M2 ;
		ANTENNAMAXAREACAR 5.2679 LAYER M2 ;
		ANTENNAPARTIALCUTAREA 0.0065 LAYER VIA2 ;
		ANTENNAMAXAREACAR 0.4592 LAYER VIA2 ;
		ANTENNAGATEAREA 0.0196 LAYER M3 ;
		ANTENNADIFFAREA 0.0360 LAYER M3 ;
		ANTENNAPARTIALMETALAREA 0.0360 LAYER M3 ;
		ANTENNAMAXAREACAR 7.1046 LAYER M3 ;
	END BWEBM[7]

	PIN BWEB[0]
		DIRECTION INPUT ;
		USE SIGNAL ;
		PORT
			LAYER M3 ;
			RECT 27.280 3.500 27.430 3.740 ;
			LAYER M2 ;
			RECT 27.280 3.500 27.430 3.740 ;
			LAYER M1 ;
			RECT 27.280 3.500 27.430 3.740 ;
		END
		ANTENNAGATEAREA 0.0196 LAYER M1 ;
		ANTENNADIFFAREA 0.0360 LAYER M1 ;
		ANTENNAPARTIALMETALAREA 0.1726 LAYER M1 ;
		ANTENNAMAXAREACAR 6.9444 LAYER M1 ;
		ANTENNAPARTIALCUTAREA 0.0165 LAYER VIA1 ;
		ANTENNAMAXAREACAR 0.4815 LAYER VIA1 ;
		ANTENNAGATEAREA 0.0196 LAYER M2 ;
		ANTENNADIFFAREA 0.0360 LAYER M2 ;
		ANTENNAPARTIALMETALAREA 0.2455 LAYER M2 ;
		ANTENNAMAXAREACAR 22.4630 LAYER M2 ;
		ANTENNAPARTIALCUTAREA 0.0065 LAYER VIA2 ;
		ANTENNAMAXAREACAR 0.9630 LAYER VIA2 ;
		ANTENNAGATEAREA 0.0196 LAYER M3 ;
		ANTENNADIFFAREA 0.0360 LAYER M3 ;
		ANTENNAPARTIALMETALAREA 0.0360 LAYER M3 ;
		ANTENNAMAXAREACAR 25.1296 LAYER M3 ;
	END BWEB[0]

	PIN BWEB[1]
		DIRECTION INPUT ;
		USE SIGNAL ;
		PORT
			LAYER M1 ;
			RECT 27.280 7.900 27.430 8.140 ;
			LAYER M3 ;
			RECT 27.280 7.900 27.430 8.140 ;
			LAYER M2 ;
			RECT 27.280 7.900 27.430 8.140 ;
		END
		ANTENNAGATEAREA 0.0196 LAYER M1 ;
		ANTENNADIFFAREA 0.0360 LAYER M1 ;
		ANTENNAPARTIALMETALAREA 0.1726 LAYER M1 ;
		ANTENNAMAXAREACAR 6.9444 LAYER M1 ;
		ANTENNAPARTIALCUTAREA 0.0165 LAYER VIA1 ;
		ANTENNAMAXAREACAR 0.4815 LAYER VIA1 ;
		ANTENNAGATEAREA 0.0196 LAYER M2 ;
		ANTENNADIFFAREA 0.0360 LAYER M2 ;
		ANTENNAPARTIALMETALAREA 0.2455 LAYER M2 ;
		ANTENNAMAXAREACAR 22.4630 LAYER M2 ;
		ANTENNAPARTIALCUTAREA 0.0065 LAYER VIA2 ;
		ANTENNAMAXAREACAR 0.9630 LAYER VIA2 ;
		ANTENNAGATEAREA 0.0196 LAYER M3 ;
		ANTENNADIFFAREA 0.0360 LAYER M3 ;
		ANTENNAPARTIALMETALAREA 0.0360 LAYER M3 ;
		ANTENNAMAXAREACAR 25.1296 LAYER M3 ;
	END BWEB[1]

	PIN BWEB[2]
		DIRECTION INPUT ;
		USE SIGNAL ;
		PORT
			LAYER M3 ;
			RECT 27.280 12.300 27.430 12.540 ;
			LAYER M2 ;
			RECT 27.280 12.300 27.430 12.540 ;
			LAYER M1 ;
			RECT 27.280 12.300 27.430 12.540 ;
		END
		ANTENNAGATEAREA 0.0196 LAYER M1 ;
		ANTENNADIFFAREA 0.0360 LAYER M1 ;
		ANTENNAPARTIALMETALAREA 0.1726 LAYER M1 ;
		ANTENNAMAXAREACAR 6.9444 LAYER M1 ;
		ANTENNAPARTIALCUTAREA 0.0165 LAYER VIA1 ;
		ANTENNAMAXAREACAR 0.4815 LAYER VIA1 ;
		ANTENNAGATEAREA 0.0196 LAYER M2 ;
		ANTENNADIFFAREA 0.0360 LAYER M2 ;
		ANTENNAPARTIALMETALAREA 0.2455 LAYER M2 ;
		ANTENNAMAXAREACAR 22.4630 LAYER M2 ;
		ANTENNAPARTIALCUTAREA 0.0065 LAYER VIA2 ;
		ANTENNAMAXAREACAR 0.9630 LAYER VIA2 ;
		ANTENNAGATEAREA 0.0196 LAYER M3 ;
		ANTENNADIFFAREA 0.0360 LAYER M3 ;
		ANTENNAPARTIALMETALAREA 0.0360 LAYER M3 ;
		ANTENNAMAXAREACAR 25.1296 LAYER M3 ;
	END BWEB[2]

	PIN BWEB[3]
		DIRECTION INPUT ;
		USE SIGNAL ;
		PORT
			LAYER M1 ;
			RECT 27.280 16.700 27.430 16.940 ;
			LAYER M3 ;
			RECT 27.280 16.700 27.430 16.940 ;
			LAYER M2 ;
			RECT 27.280 16.700 27.430 16.940 ;
		END
		ANTENNAGATEAREA 0.0196 LAYER M1 ;
		ANTENNADIFFAREA 0.0360 LAYER M1 ;
		ANTENNAPARTIALMETALAREA 0.1726 LAYER M1 ;
		ANTENNAMAXAREACAR 6.9444 LAYER M1 ;
		ANTENNAPARTIALCUTAREA 0.0165 LAYER VIA1 ;
		ANTENNAMAXAREACAR 0.4815 LAYER VIA1 ;
		ANTENNAGATEAREA 0.0196 LAYER M2 ;
		ANTENNADIFFAREA 0.0360 LAYER M2 ;
		ANTENNAPARTIALMETALAREA 0.2455 LAYER M2 ;
		ANTENNAMAXAREACAR 22.4630 LAYER M2 ;
		ANTENNAPARTIALCUTAREA 0.0065 LAYER VIA2 ;
		ANTENNAMAXAREACAR 0.9630 LAYER VIA2 ;
		ANTENNAGATEAREA 0.0196 LAYER M3 ;
		ANTENNADIFFAREA 0.0360 LAYER M3 ;
		ANTENNAPARTIALMETALAREA 0.0360 LAYER M3 ;
		ANTENNAMAXAREACAR 25.1296 LAYER M3 ;
	END BWEB[3]

	PIN BWEB[4]
		DIRECTION INPUT ;
		USE SIGNAL ;
		PORT
			LAYER M2 ;
			RECT 27.280 54.175 27.430 54.415 ;
			LAYER M1 ;
			RECT 27.280 54.175 27.430 54.415 ;
			LAYER M3 ;
			RECT 27.280 54.175 27.430 54.415 ;
		END
		ANTENNAGATEAREA 0.0196 LAYER M1 ;
		ANTENNADIFFAREA 0.0360 LAYER M1 ;
		ANTENNAPARTIALMETALAREA 0.1726 LAYER M1 ;
		ANTENNAMAXAREACAR 6.9444 LAYER M1 ;
		ANTENNAPARTIALCUTAREA 0.0165 LAYER VIA1 ;
		ANTENNAMAXAREACAR 0.4815 LAYER VIA1 ;
		ANTENNAGATEAREA 0.0196 LAYER M2 ;
		ANTENNADIFFAREA 0.0360 LAYER M2 ;
		ANTENNAPARTIALMETALAREA 0.2455 LAYER M2 ;
		ANTENNAMAXAREACAR 22.4630 LAYER M2 ;
		ANTENNAPARTIALCUTAREA 0.0065 LAYER VIA2 ;
		ANTENNAMAXAREACAR 0.9630 LAYER VIA2 ;
		ANTENNAGATEAREA 0.0196 LAYER M3 ;
		ANTENNADIFFAREA 0.0360 LAYER M3 ;
		ANTENNAPARTIALMETALAREA 0.0360 LAYER M3 ;
		ANTENNAMAXAREACAR 25.1296 LAYER M3 ;
	END BWEB[4]

	PIN BWEB[5]
		DIRECTION INPUT ;
		USE SIGNAL ;
		PORT
			LAYER M2 ;
			RECT 27.280 58.575 27.430 58.815 ;
			LAYER M1 ;
			RECT 27.280 58.575 27.430 58.815 ;
			LAYER M3 ;
			RECT 27.280 58.575 27.430 58.815 ;
		END
		ANTENNAGATEAREA 0.0196 LAYER M1 ;
		ANTENNADIFFAREA 0.0360 LAYER M1 ;
		ANTENNAPARTIALMETALAREA 0.1726 LAYER M1 ;
		ANTENNAMAXAREACAR 6.9444 LAYER M1 ;
		ANTENNAPARTIALCUTAREA 0.0165 LAYER VIA1 ;
		ANTENNAMAXAREACAR 0.4815 LAYER VIA1 ;
		ANTENNAGATEAREA 0.0196 LAYER M2 ;
		ANTENNADIFFAREA 0.0360 LAYER M2 ;
		ANTENNAPARTIALMETALAREA 0.2455 LAYER M2 ;
		ANTENNAMAXAREACAR 22.4630 LAYER M2 ;
		ANTENNAPARTIALCUTAREA 0.0065 LAYER VIA2 ;
		ANTENNAMAXAREACAR 0.9630 LAYER VIA2 ;
		ANTENNAGATEAREA 0.0196 LAYER M3 ;
		ANTENNADIFFAREA 0.0360 LAYER M3 ;
		ANTENNAPARTIALMETALAREA 0.0360 LAYER M3 ;
		ANTENNAMAXAREACAR 25.1296 LAYER M3 ;
	END BWEB[5]

	PIN BWEB[6]
		DIRECTION INPUT ;
		USE SIGNAL ;
		PORT
			LAYER M1 ;
			RECT 27.280 62.975 27.430 63.215 ;
			LAYER M3 ;
			RECT 27.280 62.975 27.430 63.215 ;
			LAYER M2 ;
			RECT 27.280 62.975 27.430 63.215 ;
		END
		ANTENNAGATEAREA 0.0196 LAYER M1 ;
		ANTENNADIFFAREA 0.0360 LAYER M1 ;
		ANTENNAPARTIALMETALAREA 0.1726 LAYER M1 ;
		ANTENNAMAXAREACAR 6.9444 LAYER M1 ;
		ANTENNAPARTIALCUTAREA 0.0165 LAYER VIA1 ;
		ANTENNAMAXAREACAR 0.4815 LAYER VIA1 ;
		ANTENNAGATEAREA 0.0196 LAYER M2 ;
		ANTENNADIFFAREA 0.0360 LAYER M2 ;
		ANTENNAPARTIALMETALAREA 0.2455 LAYER M2 ;
		ANTENNAMAXAREACAR 22.4630 LAYER M2 ;
		ANTENNAPARTIALCUTAREA 0.0065 LAYER VIA2 ;
		ANTENNAMAXAREACAR 0.9630 LAYER VIA2 ;
		ANTENNAGATEAREA 0.0196 LAYER M3 ;
		ANTENNADIFFAREA 0.0360 LAYER M3 ;
		ANTENNAPARTIALMETALAREA 0.0360 LAYER M3 ;
		ANTENNAMAXAREACAR 25.1296 LAYER M3 ;
	END BWEB[6]

	PIN BWEB[7]
		DIRECTION INPUT ;
		USE SIGNAL ;
		PORT
			LAYER M2 ;
			RECT 27.280 67.375 27.430 67.615 ;
			LAYER M1 ;
			RECT 27.280 67.375 27.430 67.615 ;
			LAYER M3 ;
			RECT 27.280 67.375 27.430 67.615 ;
		END
		ANTENNAGATEAREA 0.0196 LAYER M1 ;
		ANTENNADIFFAREA 0.0360 LAYER M1 ;
		ANTENNAPARTIALMETALAREA 0.1726 LAYER M1 ;
		ANTENNAMAXAREACAR 6.9444 LAYER M1 ;
		ANTENNAPARTIALCUTAREA 0.0165 LAYER VIA1 ;
		ANTENNAMAXAREACAR 0.4815 LAYER VIA1 ;
		ANTENNAGATEAREA 0.0196 LAYER M2 ;
		ANTENNADIFFAREA 0.0360 LAYER M2 ;
		ANTENNAPARTIALMETALAREA 0.2455 LAYER M2 ;
		ANTENNAMAXAREACAR 22.4630 LAYER M2 ;
		ANTENNAPARTIALCUTAREA 0.0065 LAYER VIA2 ;
		ANTENNAMAXAREACAR 0.9630 LAYER VIA2 ;
		ANTENNAGATEAREA 0.0196 LAYER M3 ;
		ANTENNADIFFAREA 0.0360 LAYER M3 ;
		ANTENNAPARTIALMETALAREA 0.0360 LAYER M3 ;
		ANTENNAMAXAREACAR 25.1296 LAYER M3 ;
	END BWEB[7]

	PIN CLKR
		DIRECTION INPUT ;
		USE SIGNAL ;
		PORT
			LAYER M3 ;
			RECT 27.280 34.750 27.430 34.990 ;
			LAYER M1 ;
			RECT 27.280 34.750 27.430 34.990 ;
			LAYER M2 ;
			RECT 27.280 34.750 27.430 34.990 ;
		END
		ANTENNAGATEAREA 0.2613 LAYER M1 ;
		ANTENNADIFFAREA 0.0360 LAYER M1 ;
		ANTENNAPARTIALMETALAREA 0.3871 LAYER M1 ;
		ANTENNAMAXAREACAR 3.7037 LAYER M1 ;
		ANTENNAPARTIALCUTAREA 0.0515 LAYER VIA1 ;
		ANTENNAMAXAREACAR 0.6019 LAYER VIA1 ;
		ANTENNAGATEAREA 0.2613 LAYER M2 ;
		ANTENNADIFFAREA 0.0360 LAYER M2 ;
		ANTENNAPARTIALMETALAREA 1.3928 LAYER M2 ;
		ANTENNAMAXAREACAR 15.3139 LAYER M2 ;
		ANTENNAPARTIALCUTAREA 0.0190 LAYER VIA2 ;
		ANTENNAMAXAREACAR 0.9352 LAYER VIA2 ;
		ANTENNAGATEAREA 0.2613 LAYER M3 ;
		ANTENNADIFFAREA 0.0360 LAYER M3 ;
		ANTENNAPARTIALMETALAREA 0.5928 LAYER M3 ;
		ANTENNAMAXAREACAR 17.5827 LAYER M3 ;
	END CLKR

	PIN CLKW
		DIRECTION INPUT ;
		USE SIGNAL ;
		PORT
			LAYER M3 ;
			RECT 27.280 35.520 27.430 35.760 ;
			LAYER M2 ;
			RECT 27.280 35.520 27.430 35.760 ;
			LAYER M1 ;
			RECT 27.280 35.520 27.430 35.760 ;
		END
		ANTENNAGATEAREA 0.2136 LAYER M1 ;
		ANTENNADIFFAREA 0.0360 LAYER M1 ;
		ANTENNAPARTIALMETALAREA 0.4068 LAYER M1 ;
		ANTENNAMAXAREACAR 6.1384 LAYER M1 ;
		ANTENNAPARTIALCUTAREA 0.0345 LAYER VIA1 ;
		ANTENNAMAXAREACAR 0.6019 LAYER VIA1 ;
		ANTENNAGATEAREA 0.2136 LAYER M2 ;
		ANTENNADIFFAREA 0.0360 LAYER M2 ;
		ANTENNAPARTIALMETALAREA 1.1042 LAYER M2 ;
		ANTENNAMAXAREACAR 14.0860 LAYER M2 ;
		ANTENNAPARTIALCUTAREA 0.0140 LAYER VIA2 ;
		ANTENNAMAXAREACAR 0.9352 LAYER VIA2 ;
		ANTENNAGATEAREA 0.2136 LAYER M3 ;
		ANTENNADIFFAREA 0.0360 LAYER M3 ;
		ANTENNAPARTIALMETALAREA 0.3577 LAYER M3 ;
		ANTENNAMAXAREACAR 15.2289 LAYER M3 ;
	END CLKW

	PIN DM[0]
		DIRECTION INPUT ;
		USE SIGNAL ;
		PORT
			LAYER M3 ;
			RECT 27.280 4.280 27.430 4.520 ;
			LAYER M2 ;
			RECT 27.280 4.280 27.430 4.520 ;
			LAYER M1 ;
			RECT 27.280 4.280 27.430 4.520 ;
		END
		ANTENNAGATEAREA 0.0196 LAYER M1 ;
		ANTENNADIFFAREA 0.0360 LAYER M1 ;
		ANTENNAPARTIALMETALAREA 0.0945 LAYER M1 ;
		ANTENNAMAXAREACAR 0.8036 LAYER M1 ;
		ANTENNAPARTIALCUTAREA 0.0115 LAYER VIA1 ;
		ANTENNAMAXAREACAR 0.1276 LAYER VIA1 ;
		ANTENNAGATEAREA 0.0196 LAYER M2 ;
		ANTENNADIFFAREA 0.0360 LAYER M2 ;
		ANTENNAPARTIALMETALAREA 0.0875 LAYER M2 ;
		ANTENNAMAXAREACAR 5.2679 LAYER M2 ;
		ANTENNAPARTIALCUTAREA 0.0065 LAYER VIA2 ;
		ANTENNAMAXAREACAR 0.4592 LAYER VIA2 ;
		ANTENNAGATEAREA 0.0196 LAYER M3 ;
		ANTENNADIFFAREA 0.0360 LAYER M3 ;
		ANTENNAPARTIALMETALAREA 0.0360 LAYER M3 ;
		ANTENNAMAXAREACAR 7.1046 LAYER M3 ;
	END DM[0]

	PIN DM[1]
		DIRECTION INPUT ;
		USE SIGNAL ;
		PORT
			LAYER M2 ;
			RECT 27.280 8.680 27.430 8.920 ;
			LAYER M3 ;
			RECT 27.280 8.680 27.430 8.920 ;
			LAYER M1 ;
			RECT 27.280 8.680 27.430 8.920 ;
		END
		ANTENNAGATEAREA 0.0196 LAYER M1 ;
		ANTENNADIFFAREA 0.0360 LAYER M1 ;
		ANTENNAPARTIALMETALAREA 0.0945 LAYER M1 ;
		ANTENNAMAXAREACAR 0.8036 LAYER M1 ;
		ANTENNAPARTIALCUTAREA 0.0115 LAYER VIA1 ;
		ANTENNAMAXAREACAR 0.1276 LAYER VIA1 ;
		ANTENNAGATEAREA 0.0196 LAYER M2 ;
		ANTENNADIFFAREA 0.0360 LAYER M2 ;
		ANTENNAPARTIALMETALAREA 0.0875 LAYER M2 ;
		ANTENNAMAXAREACAR 5.2679 LAYER M2 ;
		ANTENNAPARTIALCUTAREA 0.0065 LAYER VIA2 ;
		ANTENNAMAXAREACAR 0.4592 LAYER VIA2 ;
		ANTENNAGATEAREA 0.0196 LAYER M3 ;
		ANTENNADIFFAREA 0.0360 LAYER M3 ;
		ANTENNAPARTIALMETALAREA 0.0360 LAYER M3 ;
		ANTENNAMAXAREACAR 7.1046 LAYER M3 ;
	END DM[1]

	PIN DM[2]
		DIRECTION INPUT ;
		USE SIGNAL ;
		PORT
			LAYER M1 ;
			RECT 27.280 13.080 27.430 13.320 ;
			LAYER M3 ;
			RECT 27.280 13.080 27.430 13.320 ;
			LAYER M2 ;
			RECT 27.280 13.080 27.430 13.320 ;
		END
		ANTENNAGATEAREA 0.0196 LAYER M1 ;
		ANTENNADIFFAREA 0.0360 LAYER M1 ;
		ANTENNAPARTIALMETALAREA 0.0945 LAYER M1 ;
		ANTENNAMAXAREACAR 0.8036 LAYER M1 ;
		ANTENNAPARTIALCUTAREA 0.0115 LAYER VIA1 ;
		ANTENNAMAXAREACAR 0.1276 LAYER VIA1 ;
		ANTENNAGATEAREA 0.0196 LAYER M2 ;
		ANTENNADIFFAREA 0.0360 LAYER M2 ;
		ANTENNAPARTIALMETALAREA 0.0875 LAYER M2 ;
		ANTENNAMAXAREACAR 5.2679 LAYER M2 ;
		ANTENNAPARTIALCUTAREA 0.0065 LAYER VIA2 ;
		ANTENNAMAXAREACAR 0.4592 LAYER VIA2 ;
		ANTENNAGATEAREA 0.0196 LAYER M3 ;
		ANTENNADIFFAREA 0.0360 LAYER M3 ;
		ANTENNAPARTIALMETALAREA 0.0360 LAYER M3 ;
		ANTENNAMAXAREACAR 7.1046 LAYER M3 ;
	END DM[2]

	PIN DM[3]
		DIRECTION INPUT ;
		USE SIGNAL ;
		PORT
			LAYER M3 ;
			RECT 27.280 17.480 27.430 17.720 ;
			LAYER M2 ;
			RECT 27.280 17.480 27.430 17.720 ;
			LAYER M1 ;
			RECT 27.280 17.480 27.430 17.720 ;
		END
		ANTENNAGATEAREA 0.0196 LAYER M1 ;
		ANTENNADIFFAREA 0.0360 LAYER M1 ;
		ANTENNAPARTIALMETALAREA 0.0945 LAYER M1 ;
		ANTENNAMAXAREACAR 0.8036 LAYER M1 ;
		ANTENNAPARTIALCUTAREA 0.0115 LAYER VIA1 ;
		ANTENNAMAXAREACAR 0.1276 LAYER VIA1 ;
		ANTENNAGATEAREA 0.0196 LAYER M2 ;
		ANTENNADIFFAREA 0.0360 LAYER M2 ;
		ANTENNAPARTIALMETALAREA 0.0875 LAYER M2 ;
		ANTENNAMAXAREACAR 5.2679 LAYER M2 ;
		ANTENNAPARTIALCUTAREA 0.0065 LAYER VIA2 ;
		ANTENNAMAXAREACAR 0.4592 LAYER VIA2 ;
		ANTENNAGATEAREA 0.0196 LAYER M3 ;
		ANTENNADIFFAREA 0.0360 LAYER M3 ;
		ANTENNAPARTIALMETALAREA 0.0360 LAYER M3 ;
		ANTENNAMAXAREACAR 7.1046 LAYER M3 ;
	END DM[3]

	PIN DM[4]
		DIRECTION INPUT ;
		USE SIGNAL ;
		PORT
			LAYER M1 ;
			RECT 27.280 53.395 27.430 53.635 ;
			LAYER M2 ;
			RECT 27.280 53.395 27.430 53.635 ;
			LAYER M3 ;
			RECT 27.280 53.395 27.430 53.635 ;
		END
		ANTENNAGATEAREA 0.0196 LAYER M1 ;
		ANTENNADIFFAREA 0.0360 LAYER M1 ;
		ANTENNAPARTIALMETALAREA 0.0945 LAYER M1 ;
		ANTENNAMAXAREACAR 0.8036 LAYER M1 ;
		ANTENNAPARTIALCUTAREA 0.0115 LAYER VIA1 ;
		ANTENNAMAXAREACAR 0.1276 LAYER VIA1 ;
		ANTENNAGATEAREA 0.0196 LAYER M2 ;
		ANTENNADIFFAREA 0.0360 LAYER M2 ;
		ANTENNAPARTIALMETALAREA 0.0875 LAYER M2 ;
		ANTENNAMAXAREACAR 5.2679 LAYER M2 ;
		ANTENNAPARTIALCUTAREA 0.0065 LAYER VIA2 ;
		ANTENNAMAXAREACAR 0.4592 LAYER VIA2 ;
		ANTENNAGATEAREA 0.0196 LAYER M3 ;
		ANTENNADIFFAREA 0.0360 LAYER M3 ;
		ANTENNAPARTIALMETALAREA 0.0360 LAYER M3 ;
		ANTENNAMAXAREACAR 7.1046 LAYER M3 ;
	END DM[4]

	PIN DM[5]
		DIRECTION INPUT ;
		USE SIGNAL ;
		PORT
			LAYER M3 ;
			RECT 27.280 57.795 27.430 58.035 ;
			LAYER M2 ;
			RECT 27.280 57.795 27.430 58.035 ;
			LAYER M1 ;
			RECT 27.280 57.795 27.430 58.035 ;
		END
		ANTENNAGATEAREA 0.0196 LAYER M1 ;
		ANTENNADIFFAREA 0.0360 LAYER M1 ;
		ANTENNAPARTIALMETALAREA 0.0945 LAYER M1 ;
		ANTENNAMAXAREACAR 0.8036 LAYER M1 ;
		ANTENNAPARTIALCUTAREA 0.0115 LAYER VIA1 ;
		ANTENNAMAXAREACAR 0.1276 LAYER VIA1 ;
		ANTENNAGATEAREA 0.0196 LAYER M2 ;
		ANTENNADIFFAREA 0.0360 LAYER M2 ;
		ANTENNAPARTIALMETALAREA 0.0875 LAYER M2 ;
		ANTENNAMAXAREACAR 5.2679 LAYER M2 ;
		ANTENNAPARTIALCUTAREA 0.0065 LAYER VIA2 ;
		ANTENNAMAXAREACAR 0.4592 LAYER VIA2 ;
		ANTENNAGATEAREA 0.0196 LAYER M3 ;
		ANTENNADIFFAREA 0.0360 LAYER M3 ;
		ANTENNAPARTIALMETALAREA 0.0360 LAYER M3 ;
		ANTENNAMAXAREACAR 7.1046 LAYER M3 ;
	END DM[5]

	PIN DM[6]
		DIRECTION INPUT ;
		USE SIGNAL ;
		PORT
			LAYER M1 ;
			RECT 27.280 62.195 27.430 62.435 ;
			LAYER M2 ;
			RECT 27.280 62.195 27.430 62.435 ;
			LAYER M3 ;
			RECT 27.280 62.195 27.430 62.435 ;
		END
		ANTENNAGATEAREA 0.0196 LAYER M1 ;
		ANTENNADIFFAREA 0.0360 LAYER M1 ;
		ANTENNAPARTIALMETALAREA 0.0945 LAYER M1 ;
		ANTENNAMAXAREACAR 0.8036 LAYER M1 ;
		ANTENNAPARTIALCUTAREA 0.0115 LAYER VIA1 ;
		ANTENNAMAXAREACAR 0.1276 LAYER VIA1 ;
		ANTENNAGATEAREA 0.0196 LAYER M2 ;
		ANTENNADIFFAREA 0.0360 LAYER M2 ;
		ANTENNAPARTIALMETALAREA 0.0875 LAYER M2 ;
		ANTENNAMAXAREACAR 5.2679 LAYER M2 ;
		ANTENNAPARTIALCUTAREA 0.0065 LAYER VIA2 ;
		ANTENNAMAXAREACAR 0.4592 LAYER VIA2 ;
		ANTENNAGATEAREA 0.0196 LAYER M3 ;
		ANTENNADIFFAREA 0.0360 LAYER M3 ;
		ANTENNAPARTIALMETALAREA 0.0360 LAYER M3 ;
		ANTENNAMAXAREACAR 7.1046 LAYER M3 ;
	END DM[6]

	PIN DM[7]
		DIRECTION INPUT ;
		USE SIGNAL ;
		PORT
			LAYER M3 ;
			RECT 27.280 66.595 27.430 66.835 ;
			LAYER M2 ;
			RECT 27.280 66.595 27.430 66.835 ;
			LAYER M1 ;
			RECT 27.280 66.595 27.430 66.835 ;
		END
		ANTENNAGATEAREA 0.0196 LAYER M1 ;
		ANTENNADIFFAREA 0.0360 LAYER M1 ;
		ANTENNAPARTIALMETALAREA 0.0945 LAYER M1 ;
		ANTENNAMAXAREACAR 0.8036 LAYER M1 ;
		ANTENNAPARTIALCUTAREA 0.0115 LAYER VIA1 ;
		ANTENNAMAXAREACAR 0.1276 LAYER VIA1 ;
		ANTENNAGATEAREA 0.0196 LAYER M2 ;
		ANTENNADIFFAREA 0.0360 LAYER M2 ;
		ANTENNAPARTIALMETALAREA 0.0875 LAYER M2 ;
		ANTENNAMAXAREACAR 5.2679 LAYER M2 ;
		ANTENNAPARTIALCUTAREA 0.0065 LAYER VIA2 ;
		ANTENNAMAXAREACAR 0.4592 LAYER VIA2 ;
		ANTENNAGATEAREA 0.0196 LAYER M3 ;
		ANTENNADIFFAREA 0.0360 LAYER M3 ;
		ANTENNAPARTIALMETALAREA 0.0360 LAYER M3 ;
		ANTENNAMAXAREACAR 7.1046 LAYER M3 ;
	END DM[7]

	PIN D[0]
		DIRECTION INPUT ;
		USE SIGNAL ;
		PORT
			LAYER M2 ;
			RECT 27.280 4.670 27.430 4.910 ;
			LAYER M3 ;
			RECT 27.280 4.670 27.430 4.910 ;
			LAYER M1 ;
			RECT 27.280 4.670 27.430 4.910 ;
		END
		ANTENNAGATEAREA 0.0196 LAYER M1 ;
		ANTENNADIFFAREA 0.0360 LAYER M1 ;
		ANTENNAPARTIALMETALAREA 0.2818 LAYER M1 ;
		ANTENNAMAXAREACAR 6.2778 LAYER M1 ;
		ANTENNAPARTIALCUTAREA 0.0255 LAYER VIA1 ;
		ANTENNAMAXAREACAR 0.4815 LAYER VIA1 ;
		ANTENNAGATEAREA 0.0196 LAYER M2 ;
		ANTENNADIFFAREA 0.0360 LAYER M2 ;
		ANTENNAPARTIALMETALAREA 0.2638 LAYER M2 ;
		ANTENNAMAXAREACAR 25.0259 LAYER M2 ;
		ANTENNAPARTIALCUTAREA 0.0065 LAYER VIA2 ;
		ANTENNAMAXAREACAR 0.9630 LAYER VIA2 ;
		ANTENNAGATEAREA 0.0196 LAYER M3 ;
		ANTENNADIFFAREA 0.0360 LAYER M3 ;
		ANTENNAPARTIALMETALAREA 0.0360 LAYER M3 ;
		ANTENNAMAXAREACAR 27.6926 LAYER M3 ;
	END D[0]

	PIN D[1]
		DIRECTION INPUT ;
		USE SIGNAL ;
		PORT
			LAYER M1 ;
			RECT 27.280 9.070 27.430 9.310 ;
			LAYER M2 ;
			RECT 27.280 9.070 27.430 9.310 ;
			LAYER M3 ;
			RECT 27.280 9.070 27.430 9.310 ;
		END
		ANTENNAGATEAREA 0.0196 LAYER M1 ;
		ANTENNADIFFAREA 0.0360 LAYER M1 ;
		ANTENNAPARTIALMETALAREA 0.2818 LAYER M1 ;
		ANTENNAMAXAREACAR 6.2778 LAYER M1 ;
		ANTENNAPARTIALCUTAREA 0.0255 LAYER VIA1 ;
		ANTENNAMAXAREACAR 0.4815 LAYER VIA1 ;
		ANTENNAGATEAREA 0.0196 LAYER M2 ;
		ANTENNADIFFAREA 0.0360 LAYER M2 ;
		ANTENNAPARTIALMETALAREA 0.2638 LAYER M2 ;
		ANTENNAMAXAREACAR 25.0259 LAYER M2 ;
		ANTENNAPARTIALCUTAREA 0.0065 LAYER VIA2 ;
		ANTENNAMAXAREACAR 0.9630 LAYER VIA2 ;
		ANTENNAGATEAREA 0.0196 LAYER M3 ;
		ANTENNADIFFAREA 0.0360 LAYER M3 ;
		ANTENNAPARTIALMETALAREA 0.0360 LAYER M3 ;
		ANTENNAMAXAREACAR 27.6926 LAYER M3 ;
	END D[1]

	PIN D[2]
		DIRECTION INPUT ;
		USE SIGNAL ;
		PORT
			LAYER M1 ;
			RECT 27.280 13.470 27.430 13.710 ;
			LAYER M3 ;
			RECT 27.280 13.470 27.430 13.710 ;
			LAYER M2 ;
			RECT 27.280 13.470 27.430 13.710 ;
		END
		ANTENNAGATEAREA 0.0196 LAYER M1 ;
		ANTENNADIFFAREA 0.0360 LAYER M1 ;
		ANTENNAPARTIALMETALAREA 0.2818 LAYER M1 ;
		ANTENNAMAXAREACAR 6.2778 LAYER M1 ;
		ANTENNAPARTIALCUTAREA 0.0255 LAYER VIA1 ;
		ANTENNAMAXAREACAR 0.4815 LAYER VIA1 ;
		ANTENNAGATEAREA 0.0196 LAYER M2 ;
		ANTENNADIFFAREA 0.0360 LAYER M2 ;
		ANTENNAPARTIALMETALAREA 0.2638 LAYER M2 ;
		ANTENNAMAXAREACAR 25.0259 LAYER M2 ;
		ANTENNAPARTIALCUTAREA 0.0065 LAYER VIA2 ;
		ANTENNAMAXAREACAR 0.9630 LAYER VIA2 ;
		ANTENNAGATEAREA 0.0196 LAYER M3 ;
		ANTENNADIFFAREA 0.0360 LAYER M3 ;
		ANTENNAPARTIALMETALAREA 0.0360 LAYER M3 ;
		ANTENNAMAXAREACAR 27.6926 LAYER M3 ;
	END D[2]

	PIN D[3]
		DIRECTION INPUT ;
		USE SIGNAL ;
		PORT
			LAYER M2 ;
			RECT 27.280 17.870 27.430 18.110 ;
			LAYER M3 ;
			RECT 27.280 17.870 27.430 18.110 ;
			LAYER M1 ;
			RECT 27.280 17.870 27.430 18.110 ;
		END
		ANTENNAGATEAREA 0.0196 LAYER M1 ;
		ANTENNADIFFAREA 0.0360 LAYER M1 ;
		ANTENNAPARTIALMETALAREA 0.2818 LAYER M1 ;
		ANTENNAMAXAREACAR 6.2778 LAYER M1 ;
		ANTENNAPARTIALCUTAREA 0.0255 LAYER VIA1 ;
		ANTENNAMAXAREACAR 0.4815 LAYER VIA1 ;
		ANTENNAGATEAREA 0.0196 LAYER M2 ;
		ANTENNADIFFAREA 0.0360 LAYER M2 ;
		ANTENNAPARTIALMETALAREA 0.2638 LAYER M2 ;
		ANTENNAMAXAREACAR 25.0259 LAYER M2 ;
		ANTENNAPARTIALCUTAREA 0.0065 LAYER VIA2 ;
		ANTENNAMAXAREACAR 0.9630 LAYER VIA2 ;
		ANTENNAGATEAREA 0.0196 LAYER M3 ;
		ANTENNADIFFAREA 0.0360 LAYER M3 ;
		ANTENNAPARTIALMETALAREA 0.0360 LAYER M3 ;
		ANTENNAMAXAREACAR 27.6926 LAYER M3 ;
	END D[3]

	PIN D[4]
		DIRECTION INPUT ;
		USE SIGNAL ;
		PORT
			LAYER M1 ;
			RECT 27.280 53.005 27.430 53.245 ;
			LAYER M2 ;
			RECT 27.280 53.005 27.430 53.245 ;
			LAYER M3 ;
			RECT 27.280 53.005 27.430 53.245 ;
		END
		ANTENNAGATEAREA 0.0196 LAYER M1 ;
		ANTENNADIFFAREA 0.0360 LAYER M1 ;
		ANTENNAPARTIALMETALAREA 0.2818 LAYER M1 ;
		ANTENNAMAXAREACAR 6.2778 LAYER M1 ;
		ANTENNAPARTIALCUTAREA 0.0255 LAYER VIA1 ;
		ANTENNAMAXAREACAR 0.4815 LAYER VIA1 ;
		ANTENNAGATEAREA 0.0196 LAYER M2 ;
		ANTENNADIFFAREA 0.0360 LAYER M2 ;
		ANTENNAPARTIALMETALAREA 0.2638 LAYER M2 ;
		ANTENNAMAXAREACAR 25.0259 LAYER M2 ;
		ANTENNAPARTIALCUTAREA 0.0065 LAYER VIA2 ;
		ANTENNAMAXAREACAR 0.9630 LAYER VIA2 ;
		ANTENNAGATEAREA 0.0196 LAYER M3 ;
		ANTENNADIFFAREA 0.0360 LAYER M3 ;
		ANTENNAPARTIALMETALAREA 0.0360 LAYER M3 ;
		ANTENNAMAXAREACAR 27.6926 LAYER M3 ;
	END D[4]

	PIN D[5]
		DIRECTION INPUT ;
		USE SIGNAL ;
		PORT
			LAYER M1 ;
			RECT 27.280 57.405 27.430 57.645 ;
			LAYER M3 ;
			RECT 27.280 57.405 27.430 57.645 ;
			LAYER M2 ;
			RECT 27.280 57.405 27.430 57.645 ;
		END
		ANTENNAGATEAREA 0.0196 LAYER M1 ;
		ANTENNADIFFAREA 0.0360 LAYER M1 ;
		ANTENNAPARTIALMETALAREA 0.2818 LAYER M1 ;
		ANTENNAMAXAREACAR 6.2778 LAYER M1 ;
		ANTENNAPARTIALCUTAREA 0.0255 LAYER VIA1 ;
		ANTENNAMAXAREACAR 0.4815 LAYER VIA1 ;
		ANTENNAGATEAREA 0.0196 LAYER M2 ;
		ANTENNADIFFAREA 0.0360 LAYER M2 ;
		ANTENNAPARTIALMETALAREA 0.2638 LAYER M2 ;
		ANTENNAMAXAREACAR 25.0259 LAYER M2 ;
		ANTENNAPARTIALCUTAREA 0.0065 LAYER VIA2 ;
		ANTENNAMAXAREACAR 0.9630 LAYER VIA2 ;
		ANTENNAGATEAREA 0.0196 LAYER M3 ;
		ANTENNADIFFAREA 0.0360 LAYER M3 ;
		ANTENNAPARTIALMETALAREA 0.0360 LAYER M3 ;
		ANTENNAMAXAREACAR 27.6926 LAYER M3 ;
	END D[5]

	PIN D[6]
		DIRECTION INPUT ;
		USE SIGNAL ;
		PORT
			LAYER M3 ;
			RECT 27.280 61.805 27.430 62.045 ;
			LAYER M1 ;
			RECT 27.280 61.805 27.430 62.045 ;
			LAYER M2 ;
			RECT 27.280 61.805 27.430 62.045 ;
		END
		ANTENNAGATEAREA 0.0196 LAYER M1 ;
		ANTENNADIFFAREA 0.0360 LAYER M1 ;
		ANTENNAPARTIALMETALAREA 0.2818 LAYER M1 ;
		ANTENNAMAXAREACAR 6.2778 LAYER M1 ;
		ANTENNAPARTIALCUTAREA 0.0255 LAYER VIA1 ;
		ANTENNAMAXAREACAR 0.4815 LAYER VIA1 ;
		ANTENNAGATEAREA 0.0196 LAYER M2 ;
		ANTENNADIFFAREA 0.0360 LAYER M2 ;
		ANTENNAPARTIALMETALAREA 0.2638 LAYER M2 ;
		ANTENNAMAXAREACAR 25.0259 LAYER M2 ;
		ANTENNAPARTIALCUTAREA 0.0065 LAYER VIA2 ;
		ANTENNAMAXAREACAR 0.9630 LAYER VIA2 ;
		ANTENNAGATEAREA 0.0196 LAYER M3 ;
		ANTENNADIFFAREA 0.0360 LAYER M3 ;
		ANTENNAPARTIALMETALAREA 0.0360 LAYER M3 ;
		ANTENNAMAXAREACAR 27.6926 LAYER M3 ;
	END D[6]

	PIN D[7]
		DIRECTION INPUT ;
		USE SIGNAL ;
		PORT
			LAYER M1 ;
			RECT 27.280 66.205 27.430 66.445 ;
			LAYER M3 ;
			RECT 27.280 66.205 27.430 66.445 ;
			LAYER M2 ;
			RECT 27.280 66.205 27.430 66.445 ;
		END
		ANTENNAGATEAREA 0.0196 LAYER M1 ;
		ANTENNADIFFAREA 0.0360 LAYER M1 ;
		ANTENNAPARTIALMETALAREA 0.2818 LAYER M1 ;
		ANTENNAMAXAREACAR 6.2778 LAYER M1 ;
		ANTENNAPARTIALCUTAREA 0.0255 LAYER VIA1 ;
		ANTENNAMAXAREACAR 0.4815 LAYER VIA1 ;
		ANTENNAGATEAREA 0.0196 LAYER M2 ;
		ANTENNADIFFAREA 0.0360 LAYER M2 ;
		ANTENNAPARTIALMETALAREA 0.2638 LAYER M2 ;
		ANTENNAMAXAREACAR 25.0259 LAYER M2 ;
		ANTENNAPARTIALCUTAREA 0.0065 LAYER VIA2 ;
		ANTENNAMAXAREACAR 0.9630 LAYER VIA2 ;
		ANTENNAGATEAREA 0.0196 LAYER M3 ;
		ANTENNADIFFAREA 0.0360 LAYER M3 ;
		ANTENNAPARTIALMETALAREA 0.0360 LAYER M3 ;
		ANTENNAMAXAREACAR 27.6926 LAYER M3 ;
	END D[7]

	PIN Q[0]
		DIRECTION OUTPUT ;
		USE SIGNAL ;
		PORT
			LAYER M3 ;
			RECT 27.280 3.100 27.430 3.340 ;
			LAYER M2 ;
			RECT 27.280 3.100 27.430 3.340 ;
			LAYER M1 ;
			RECT 27.280 3.100 27.430 3.340 ;
		END
		ANTENNADIFFAREA 0.3713 LAYER M1 ;
		ANTENNAPARTIALMETALAREA 0.6027 LAYER M1 ;
		ANTENNAPARTIALCUTAREA 0.0330 LAYER VIA1 ;
		ANTENNADIFFAREA 0.3713 LAYER M2 ;
		ANTENNAPARTIALMETALAREA 0.7662 LAYER M2 ;
		ANTENNAPARTIALCUTAREA 0.0140 LAYER VIA2 ;
		ANTENNADIFFAREA 0.3713 LAYER M3 ;
		ANTENNAPARTIALMETALAREA 0.1277 LAYER M3 ;
	END Q[0]

	PIN Q[1]
		DIRECTION OUTPUT ;
		USE SIGNAL ;
		PORT
			LAYER M3 ;
			RECT 27.280 7.500 27.430 7.740 ;
			LAYER M2 ;
			RECT 27.280 7.500 27.430 7.740 ;
			LAYER M1 ;
			RECT 27.280 7.500 27.430 7.740 ;
		END
		ANTENNADIFFAREA 0.3713 LAYER M1 ;
		ANTENNAPARTIALMETALAREA 0.6027 LAYER M1 ;
		ANTENNAPARTIALCUTAREA 0.0330 LAYER VIA1 ;
		ANTENNADIFFAREA 0.3713 LAYER M2 ;
		ANTENNAPARTIALMETALAREA 0.7662 LAYER M2 ;
		ANTENNAPARTIALCUTAREA 0.0140 LAYER VIA2 ;
		ANTENNADIFFAREA 0.3713 LAYER M3 ;
		ANTENNAPARTIALMETALAREA 0.1277 LAYER M3 ;
	END Q[1]

	PIN Q[2]
		DIRECTION OUTPUT ;
		USE SIGNAL ;
		PORT
			LAYER M1 ;
			RECT 27.280 11.900 27.430 12.140 ;
			LAYER M2 ;
			RECT 27.280 11.900 27.430 12.140 ;
			LAYER M3 ;
			RECT 27.280 11.900 27.430 12.140 ;
		END
		ANTENNADIFFAREA 0.3713 LAYER M1 ;
		ANTENNAPARTIALMETALAREA 0.6027 LAYER M1 ;
		ANTENNAPARTIALCUTAREA 0.0330 LAYER VIA1 ;
		ANTENNADIFFAREA 0.3713 LAYER M2 ;
		ANTENNAPARTIALMETALAREA 0.7662 LAYER M2 ;
		ANTENNAPARTIALCUTAREA 0.0140 LAYER VIA2 ;
		ANTENNADIFFAREA 0.3713 LAYER M3 ;
		ANTENNAPARTIALMETALAREA 0.1277 LAYER M3 ;
	END Q[2]

	PIN Q[3]
		DIRECTION OUTPUT ;
		USE SIGNAL ;
		PORT
			LAYER M3 ;
			RECT 27.280 16.300 27.430 16.540 ;
			LAYER M2 ;
			RECT 27.280 16.300 27.430 16.540 ;
			LAYER M1 ;
			RECT 27.280 16.300 27.430 16.540 ;
		END
		ANTENNADIFFAREA 0.3713 LAYER M1 ;
		ANTENNAPARTIALMETALAREA 0.6027 LAYER M1 ;
		ANTENNAPARTIALCUTAREA 0.0330 LAYER VIA1 ;
		ANTENNADIFFAREA 0.3713 LAYER M2 ;
		ANTENNAPARTIALMETALAREA 0.7662 LAYER M2 ;
		ANTENNAPARTIALCUTAREA 0.0140 LAYER VIA2 ;
		ANTENNADIFFAREA 0.3713 LAYER M3 ;
		ANTENNAPARTIALMETALAREA 0.1277 LAYER M3 ;
	END Q[3]

	PIN Q[4]
		DIRECTION OUTPUT ;
		USE SIGNAL ;
		PORT
			LAYER M1 ;
			RECT 27.280 54.575 27.430 54.815 ;
			LAYER M3 ;
			RECT 27.280 54.575 27.430 54.815 ;
			LAYER M2 ;
			RECT 27.280 54.575 27.430 54.815 ;
		END
		ANTENNADIFFAREA 0.3713 LAYER M1 ;
		ANTENNAPARTIALMETALAREA 0.6027 LAYER M1 ;
		ANTENNAPARTIALCUTAREA 0.0330 LAYER VIA1 ;
		ANTENNADIFFAREA 0.3713 LAYER M2 ;
		ANTENNAPARTIALMETALAREA 0.7662 LAYER M2 ;
		ANTENNAPARTIALCUTAREA 0.0140 LAYER VIA2 ;
		ANTENNADIFFAREA 0.3713 LAYER M3 ;
		ANTENNAPARTIALMETALAREA 0.1277 LAYER M3 ;
	END Q[4]

	PIN Q[5]
		DIRECTION OUTPUT ;
		USE SIGNAL ;
		PORT
			LAYER M1 ;
			RECT 27.280 58.975 27.430 59.215 ;
			LAYER M2 ;
			RECT 27.280 58.975 27.430 59.215 ;
			LAYER M3 ;
			RECT 27.280 58.975 27.430 59.215 ;
		END
		ANTENNADIFFAREA 0.3713 LAYER M1 ;
		ANTENNAPARTIALMETALAREA 0.6027 LAYER M1 ;
		ANTENNAPARTIALCUTAREA 0.0330 LAYER VIA1 ;
		ANTENNADIFFAREA 0.3713 LAYER M2 ;
		ANTENNAPARTIALMETALAREA 0.7662 LAYER M2 ;
		ANTENNAPARTIALCUTAREA 0.0140 LAYER VIA2 ;
		ANTENNADIFFAREA 0.3713 LAYER M3 ;
		ANTENNAPARTIALMETALAREA 0.1277 LAYER M3 ;
	END Q[5]

	PIN Q[6]
		DIRECTION OUTPUT ;
		USE SIGNAL ;
		PORT
			LAYER M1 ;
			RECT 27.280 63.375 27.430 63.615 ;
			LAYER M2 ;
			RECT 27.280 63.375 27.430 63.615 ;
			LAYER M3 ;
			RECT 27.280 63.375 27.430 63.615 ;
		END
		ANTENNADIFFAREA 0.3713 LAYER M1 ;
		ANTENNAPARTIALMETALAREA 0.6027 LAYER M1 ;
		ANTENNAPARTIALCUTAREA 0.0330 LAYER VIA1 ;
		ANTENNADIFFAREA 0.3713 LAYER M2 ;
		ANTENNAPARTIALMETALAREA 0.7662 LAYER M2 ;
		ANTENNAPARTIALCUTAREA 0.0140 LAYER VIA2 ;
		ANTENNADIFFAREA 0.3713 LAYER M3 ;
		ANTENNAPARTIALMETALAREA 0.1277 LAYER M3 ;
	END Q[6]

	PIN Q[7]
		DIRECTION OUTPUT ;
		USE SIGNAL ;
		PORT
			LAYER M1 ;
			RECT 27.280 67.775 27.430 68.015 ;
			LAYER M3 ;
			RECT 27.280 67.775 27.430 68.015 ;
			LAYER M2 ;
			RECT 27.280 67.775 27.430 68.015 ;
		END
		ANTENNADIFFAREA 0.3713 LAYER M1 ;
		ANTENNAPARTIALMETALAREA 0.6027 LAYER M1 ;
		ANTENNAPARTIALCUTAREA 0.0330 LAYER VIA1 ;
		ANTENNADIFFAREA 0.3713 LAYER M2 ;
		ANTENNAPARTIALMETALAREA 0.7662 LAYER M2 ;
		ANTENNAPARTIALCUTAREA 0.0140 LAYER VIA2 ;
		ANTENNADIFFAREA 0.3713 LAYER M3 ;
		ANTENNAPARTIALMETALAREA 0.1277 LAYER M3 ;
	END Q[7]

	PIN REB
		DIRECTION INPUT ;
		USE SIGNAL ;
		PORT
			LAYER M3 ;
			RECT 27.280 28.620 27.430 28.860 ;
			LAYER M1 ;
			RECT 27.280 28.620 27.430 28.860 ;
			LAYER M2 ;
			RECT 27.280 28.620 27.430 28.860 ;
		END
		ANTENNAGATEAREA 0.0504 LAYER M1 ;
		ANTENNADIFFAREA 0.0360 LAYER M1 ;
		ANTENNAPARTIALMETALAREA 0.1066 LAYER M1 ;
		ANTENNAMAXAREACAR 0.9987 LAYER M1 ;
		ANTENNAPARTIALCUTAREA 0.0155 LAYER VIA1 ;
		ANTENNAMAXAREACAR 0.1290 LAYER VIA1 ;
		ANTENNAGATEAREA 0.0504 LAYER M2 ;
		ANTENNADIFFAREA 0.0360 LAYER M2 ;
		ANTENNAPARTIALMETALAREA 0.5864 LAYER M2 ;
		ANTENNAMAXAREACAR 12.1845 LAYER M2 ;
		ANTENNAPARTIALCUTAREA 0.0065 LAYER VIA2 ;
		ANTENNAMAXAREACAR 0.4592 LAYER VIA2 ;
		ANTENNAGATEAREA 0.0504 LAYER M3 ;
		ANTENNADIFFAREA 0.0360 LAYER M3 ;
		ANTENNAPARTIALMETALAREA 0.0360 LAYER M3 ;
		ANTENNAMAXAREACAR 12.8988 LAYER M3 ;
	END REB

	PIN REBM
		DIRECTION INPUT ;
		USE SIGNAL ;
		PORT
			LAYER M1 ;
			RECT 27.280 29.010 27.430 29.250 ;
			LAYER M3 ;
			RECT 27.280 29.010 27.430 29.250 ;
			LAYER M2 ;
			RECT 27.280 29.010 27.430 29.250 ;
		END
		ANTENNAGATEAREA 0.0196 LAYER M1 ;
		ANTENNADIFFAREA 0.0360 LAYER M1 ;
		ANTENNAPARTIALMETALAREA 0.0945 LAYER M1 ;
		ANTENNAMAXAREACAR 0.8036 LAYER M1 ;
		ANTENNAPARTIALCUTAREA 0.0115 LAYER VIA1 ;
		ANTENNAMAXAREACAR 0.1276 LAYER VIA1 ;
		ANTENNAGATEAREA 0.0196 LAYER M2 ;
		ANTENNADIFFAREA 0.0360 LAYER M2 ;
		ANTENNAPARTIALMETALAREA 0.0795 LAYER M2 ;
		ANTENNAMAXAREACAR 4.8597 LAYER M2 ;
		ANTENNAPARTIALCUTAREA 0.0065 LAYER VIA2 ;
		ANTENNAMAXAREACAR 0.4592 LAYER VIA2 ;
		ANTENNAGATEAREA 0.0196 LAYER M3 ;
		ANTENNADIFFAREA 0.0360 LAYER M3 ;
		ANTENNAPARTIALMETALAREA 0.0360 LAYER M3 ;
		ANTENNAMAXAREACAR 6.6964 LAYER M3 ;
	END REBM

	PIN SD
		DIRECTION INPUT ;
		USE SIGNAL ;
		PORT
			LAYER M3 ;
			RECT 27.280 36.200 27.430 36.440 ;
			LAYER M2 ;
			RECT 27.280 36.200 27.430 36.440 ;
			LAYER M1 ;
			RECT 27.280 36.200 27.430 36.440 ;
		END
		ANTENNAGATEAREA 0.2616 LAYER M1 ;
		ANTENNADIFFAREA 0.0360 LAYER M1 ;
		ANTENNAPARTIALMETALAREA 0.6831 LAYER M1 ;
		ANTENNAMAXAREACAR 12.9670 LAYER M1 ;
		ANTENNAPARTIALCUTAREA 0.0230 LAYER VIA1 ;
		ANTENNAMAXAREACAR 0.2747 LAYER VIA1 ;
		ANTENNAGATEAREA 0.2616 LAYER M2 ;
		ANTENNADIFFAREA 0.0360 LAYER M2 ;
		ANTENNAPARTIALMETALAREA 1.4003 LAYER M2 ;
		ANTENNAMAXAREACAR 163.8790 LAYER M2 ;
		ANTENNAPARTIALCUTAREA 0.0165 LAYER VIA2 ;
		ANTENNAMAXAREACAR 1.2637 LAYER VIA2 ;
		ANTENNAGATEAREA 0.2616 LAYER M3 ;
		ANTENNADIFFAREA 0.0360 LAYER M3 ;
		ANTENNAPARTIALMETALAREA 0.4299 LAYER M3 ;
		ANTENNAMAXAREACAR 164.6450 LAYER M3 ;
	END SD

	PIN SLP
		DIRECTION INPUT ;
		USE SIGNAL ;
		PORT
			LAYER M1 ;
			RECT 27.280 37.670 27.430 37.910 ;
			LAYER M3 ;
			RECT 27.280 37.670 27.430 37.910 ;
			LAYER M2 ;
			RECT 27.280 37.670 27.430 37.910 ;
		END
		ANTENNAGATEAREA 0.0616 LAYER M1 ;
		ANTENNADIFFAREA 0.0360 LAYER M1 ;
		ANTENNAPARTIALMETALAREA 0.3388 LAYER M1 ;
		ANTENNAMAXAREACAR 20.4121 LAYER M1 ;
		ANTENNAPARTIALCUTAREA 0.0230 LAYER VIA1 ;
		ANTENNAMAXAREACAR 0.2747 LAYER VIA1 ;
		ANTENNAGATEAREA 0.0616 LAYER M2 ;
		ANTENNADIFFAREA 0.0360 LAYER M2 ;
		ANTENNAPARTIALMETALAREA 1.3864 LAYER M2 ;
		ANTENNAMAXAREACAR 165.4560 LAYER M2 ;
		ANTENNAPARTIALCUTAREA 0.0115 LAYER VIA2 ;
		ANTENNAMAXAREACAR 1.2637 LAYER VIA2 ;
		ANTENNAGATEAREA 0.0616 LAYER M3 ;
		ANTENNADIFFAREA 0.0360 LAYER M3 ;
		ANTENNAPARTIALMETALAREA 0.5889 LAYER M3 ;
		ANTENNAMAXAREACAR 175.0160 LAYER M3 ;
	END SLP

	PIN VDD
		DIRECTION INOUT ;
		USE POWER ;
		PORT
			LAYER M4 ;
			RECT 0.000 1.740 27.430 2.160 ;
			LAYER M4 ;
			RECT 0.000 3.940 27.430 4.360 ;
			LAYER M4 ;
			RECT 0.000 6.140 27.430 6.560 ;
			LAYER M4 ;
			RECT 0.000 8.340 27.430 8.760 ;
			LAYER M4 ;
			RECT 0.000 10.540 27.430 10.960 ;
			LAYER M4 ;
			RECT 0.000 12.740 27.430 13.160 ;
			LAYER M4 ;
			RECT 0.000 14.940 27.430 15.360 ;
			LAYER M4 ;
			RECT 0.000 17.140 27.430 17.560 ;
			LAYER M4 ;
			RECT 0.000 19.340 27.430 19.760 ;
			LAYER M4 ;
			RECT 0.000 24.070 27.430 24.570 ;
			LAYER M4 ;
			RECT 0.000 27.470 27.430 28.070 ;
			LAYER M4 ;
			RECT 0.000 29.380 27.430 29.980 ;
			LAYER M4 ;
			RECT 0.000 32.320 27.430 32.770 ;
			LAYER M4 ;
			RECT 0.000 35.080 27.430 35.530 ;
			LAYER M4 ;
			RECT 0.000 37.870 27.430 38.470 ;
			LAYER M4 ;
			RECT 0.000 39.780 27.430 40.380 ;
			LAYER M4 ;
			RECT 0.000 43.280 27.430 43.780 ;
			LAYER M4 ;
			RECT 0.000 48.180 27.430 48.600 ;
			LAYER M4 ;
			RECT 0.000 51.355 27.430 51.775 ;
			LAYER M4 ;
			RECT 0.000 53.555 27.430 53.975 ;
			LAYER M4 ;
			RECT 0.000 55.755 27.430 56.175 ;
			LAYER M4 ;
			RECT 0.000 57.955 27.430 58.375 ;
			LAYER M4 ;
			RECT 0.000 60.155 27.430 60.575 ;
			LAYER M4 ;
			RECT 0.000 62.355 27.430 62.775 ;
			LAYER M4 ;
			RECT 0.000 64.555 27.430 64.975 ;
			LAYER M4 ;
			RECT 0.000 66.755 27.430 67.175 ;
			LAYER M4 ;
			RECT 0.000 68.955 27.430 69.375 ;
		END
	END VDD

	PIN VSS
		DIRECTION INOUT ;
		USE GROUND ;
		PORT
			LAYER M4 ;
			RECT 0.000 0.640 27.430 1.060 ;
			LAYER M4 ;
			RECT 0.000 2.840 27.430 3.260 ;
			LAYER M4 ;
			RECT 0.000 5.040 27.430 5.460 ;
			LAYER M4 ;
			RECT 0.000 7.240 27.430 7.660 ;
			LAYER M4 ;
			RECT 0.000 9.440 27.430 9.860 ;
			LAYER M4 ;
			RECT 0.000 11.640 27.430 12.060 ;
			LAYER M4 ;
			RECT 0.000 13.840 27.430 14.260 ;
			LAYER M4 ;
			RECT 0.000 16.040 27.430 16.460 ;
			LAYER M4 ;
			RECT 0.000 18.240 27.430 18.660 ;
			LAYER M4 ;
			RECT 0.000 20.440 27.430 20.860 ;
			LAYER M4 ;
			RECT 0.000 21.090 27.430 21.510 ;
			LAYER M4 ;
			RECT 0.000 25.330 27.430 25.830 ;
			LAYER M4 ;
			RECT 0.000 30.110 27.430 30.610 ;
			LAYER M4 ;
			RECT 0.000 33.400 27.430 34.450 ;
			LAYER M4 ;
			RECT 0.000 37.240 27.430 37.740 ;
			LAYER M4 ;
			RECT 0.000 42.020 27.430 42.520 ;
			LAYER M4 ;
			RECT 0.000 46.340 27.430 46.760 ;
			LAYER M4 ;
			RECT 0.000 50.255 27.430 50.675 ;
			LAYER M4 ;
			RECT 0.000 52.455 27.430 52.875 ;
			LAYER M4 ;
			RECT 0.000 54.655 27.430 55.075 ;
			LAYER M4 ;
			RECT 0.000 56.855 27.430 57.275 ;
			LAYER M4 ;
			RECT 0.000 59.055 27.430 59.475 ;
			LAYER M4 ;
			RECT 0.000 61.255 27.430 61.675 ;
			LAYER M4 ;
			RECT 0.000 63.455 27.430 63.875 ;
			LAYER M4 ;
			RECT 0.000 65.655 27.430 66.075 ;
			LAYER M4 ;
			RECT 0.000 67.855 27.430 68.275 ;
			LAYER M4 ;
			RECT 0.000 70.055 27.430 70.475 ;
		END
	END VSS

	PIN WEB
		DIRECTION INPUT ;
		USE SIGNAL ;
		PORT
			LAYER M3 ;
			RECT 27.280 42.250 27.430 42.490 ;
			LAYER M1 ;
			RECT 27.280 42.250 27.430 42.490 ;
			LAYER M2 ;
			RECT 27.280 42.250 27.430 42.490 ;
		END
		ANTENNAGATEAREA 0.0504 LAYER M1 ;
		ANTENNADIFFAREA 0.0360 LAYER M1 ;
		ANTENNAPARTIALMETALAREA 0.1226 LAYER M1 ;
		ANTENNAMAXAREACAR 0.9987 LAYER M1 ;
		ANTENNAPARTIALCUTAREA 0.0220 LAYER VIA1 ;
		ANTENNAMAXAREACAR 0.2579 LAYER VIA1 ;
		ANTENNAGATEAREA 0.0504 LAYER M2 ;
		ANTENNADIFFAREA 0.0360 LAYER M2 ;
		ANTENNAPARTIALMETALAREA 0.6054 LAYER M2 ;
		ANTENNAMAXAREACAR 12.2986 LAYER M2 ;
		ANTENNAPARTIALCUTAREA 0.0065 LAYER VIA2 ;
		ANTENNAMAXAREACAR 0.4592 LAYER VIA2 ;
		ANTENNAGATEAREA 0.0504 LAYER M3 ;
		ANTENNADIFFAREA 0.0360 LAYER M3 ;
		ANTENNAPARTIALMETALAREA 0.0360 LAYER M3 ;
		ANTENNAMAXAREACAR 13.0129 LAYER M3 ;
	END WEB

	PIN WEBM
		DIRECTION INPUT ;
		USE SIGNAL ;
		PORT
			LAYER M1 ;
			RECT 27.280 41.835 27.430 42.075 ;
			LAYER M2 ;
			RECT 27.280 41.835 27.430 42.075 ;
			LAYER M3 ;
			RECT 27.280 41.835 27.430 42.075 ;
		END
		ANTENNAGATEAREA 0.0196 LAYER M1 ;
		ANTENNADIFFAREA 0.0360 LAYER M1 ;
		ANTENNAPARTIALMETALAREA 0.0945 LAYER M1 ;
		ANTENNAMAXAREACAR 0.8036 LAYER M1 ;
		ANTENNAPARTIALCUTAREA 0.0115 LAYER VIA1 ;
		ANTENNAMAXAREACAR 0.1276 LAYER VIA1 ;
		ANTENNAGATEAREA 0.0196 LAYER M2 ;
		ANTENNADIFFAREA 0.0360 LAYER M2 ;
		ANTENNAPARTIALMETALAREA 0.0816 LAYER M2 ;
		ANTENNAMAXAREACAR 4.9668 LAYER M2 ;
		ANTENNAPARTIALCUTAREA 0.0065 LAYER VIA2 ;
		ANTENNAMAXAREACAR 0.4592 LAYER VIA2 ;
		ANTENNAGATEAREA 0.0196 LAYER M3 ;
		ANTENNADIFFAREA 0.0360 LAYER M3 ;
		ANTENNAPARTIALMETALAREA 0.0360 LAYER M3 ;
		ANTENNAMAXAREACAR 6.8036 LAYER M3 ;
	END WEBM

	OBS
		# Promoted blockages
		LAYER M1 ;
		RECT 27.280 63.715 27.430 66.105 ;
		LAYER M2 ;
		RECT 27.280 59.315 27.430 61.705 ;
		LAYER M3 ;
		RECT 27.280 59.315 27.430 61.705 ;
		LAYER M2 ;
		RECT 27.280 29.350 27.430 33.990 ;
		LAYER M1 ;
		RECT 27.280 9.410 27.430 11.800 ;
		LAYER M2 ;
		RECT 27.280 9.410 27.430 11.800 ;
		LAYER M1 ;
		RECT 27.280 5.010 27.430 7.400 ;
		LAYER M2 ;
		RECT 27.280 5.010 27.430 7.400 ;
		LAYER M1 ;
		RECT 27.280 13.810 27.430 16.200 ;
		LAYER M2 ;
		RECT 27.280 13.810 27.430 16.200 ;
		LAYER M2 ;
		RECT 27.280 25.890 27.430 26.390 ;
		LAYER M3 ;
		RECT 27.280 29.350 27.430 33.990 ;
		LAYER M2 ;
		RECT 27.280 0.000 27.430 3.000 ;
		LAYER M1 ;
		RECT 27.280 0.000 27.430 3.000 ;
		LAYER M3 ;
		RECT 27.280 0.000 27.430 3.000 ;
		LAYER M1 ;
		RECT 27.280 50.305 27.430 51.610 ;
		LAYER M2 ;
		RECT 27.280 50.305 27.430 51.610 ;
		LAYER M3 ;
		RECT 27.280 50.305 27.430 51.610 ;
		LAYER M1 ;
		RECT 27.280 48.985 27.430 49.480 ;
		LAYER M2 ;
		RECT 27.280 48.985 27.430 49.480 ;
		LAYER M3 ;
		RECT 27.280 48.985 27.430 49.480 ;
		LAYER M2 ;
		RECT 27.280 35.090 27.430 35.420 ;
		LAYER M3 ;
		RECT 27.280 34.430 27.430 34.650 ;
		LAYER M2 ;
		RECT 27.280 34.430 27.430 34.650 ;
		LAYER M1 ;
		RECT 27.280 34.430 27.430 34.650 ;
		LAYER M3 ;
		RECT 27.280 35.090 27.430 35.420 ;
		LAYER M3 ;
		RECT 27.280 46.045 27.430 47.350 ;
		LAYER M2 ;
		RECT 27.280 52.465 27.430 52.905 ;
		LAYER M2 ;
		RECT 27.280 39.655 27.430 41.735 ;
		LAYER M3 ;
		RECT 27.280 52.465 27.430 52.905 ;
		LAYER M1 ;
		RECT 27.280 35.090 27.430 35.420 ;
		LAYER M3 ;
		RECT 27.280 54.915 27.430 57.305 ;
		LAYER M1 ;
		RECT 27.280 52.465 27.430 52.905 ;
		LAYER M1 ;
		RECT 27.280 54.915 27.430 57.305 ;
		LAYER M1 ;
		RECT 27.280 29.350 27.430 33.990 ;
		LAYER M3 ;
		RECT 27.280 27.215 27.430 28.520 ;
		LAYER M1 ;
		RECT 27.280 25.890 27.430 26.390 ;
		LAYER M3 ;
		RECT 27.280 25.890 27.430 26.390 ;
		LAYER M1 ;
		RECT 27.280 27.215 27.430 28.520 ;
		LAYER M2 ;
		RECT 27.280 27.215 27.430 28.520 ;
		LAYER M1 ;
		RECT 27.280 23.760 27.430 25.060 ;
		LAYER M2 ;
		RECT 27.280 18.210 27.430 18.645 ;
		LAYER M2 ;
		RECT 27.280 19.500 27.430 20.805 ;
		LAYER M2 ;
		RECT 27.280 23.760 27.430 25.060 ;
		LAYER M3 ;
		RECT 27.280 23.760 27.430 25.060 ;
		LAYER M3 ;
		RECT 27.280 18.210 27.430 18.645 ;
		LAYER M1 ;
		RECT 27.280 21.630 27.430 22.130 ;
		LAYER M2 ;
		RECT 27.280 21.630 27.430 22.130 ;
		LAYER M3 ;
		RECT 27.280 21.630 27.430 22.130 ;
		LAYER M1 ;
		RECT 27.280 19.500 27.430 20.805 ;
		LAYER M1 ;
		RECT 27.280 46.045 27.430 47.350 ;
		LAYER M2 ;
		RECT 27.280 46.045 27.430 47.350 ;
		LAYER M3 ;
		RECT 27.280 39.655 27.430 41.735 ;
		LAYER M1 ;
		RECT 27.280 42.590 27.430 45.220 ;
		LAYER M2 ;
		RECT 27.280 42.590 27.430 45.220 ;
		LAYER M3 ;
		RECT 27.280 42.590 27.430 45.220 ;
		LAYER M1 ;
		RECT 27.280 39.655 27.430 41.735 ;
		LAYER M1 ;
		RECT 27.280 35.860 27.430 36.100 ;
		LAYER M1 ;
		RECT 27.280 36.540 27.430 37.570 ;
		LAYER M2 ;
		RECT 27.280 36.540 27.430 37.570 ;
		LAYER M3 ;
		RECT 27.280 36.540 27.430 37.570 ;
		LAYER M2 ;
		RECT 27.280 35.860 27.430 36.100 ;
		LAYER M3 ;
		RECT 27.280 35.860 27.430 36.100 ;
		LAYER M1 ;
		RECT 27.280 38.010 27.430 38.830 ;
		LAYER M2 ;
		RECT 27.280 38.010 27.430 38.830 ;
		LAYER M3 ;
		RECT 27.280 38.010 27.430 38.830 ;
		LAYER M2 ;
		RECT 27.280 63.715 27.430 66.105 ;
		LAYER M3 ;
		RECT 27.280 63.715 27.430 66.105 ;
		LAYER M1 ;
		RECT 27.280 68.115 27.430 71.115 ;
		LAYER M2 ;
		RECT 27.280 54.915 27.430 57.305 ;
		LAYER M2 ;
		RECT 27.280 68.115 27.430 71.115 ;
		LAYER M3 ;
		RECT 27.280 68.115 27.430 71.115 ;
		LAYER M4 ;
		RECT 0.000 67.275 27.430 67.755 ;
		LAYER M4 ;
		RECT 0.000 62.875 27.430 63.355 ;
		LAYER M4 ;
		RECT 0.000 61.775 27.430 62.255 ;
		LAYER M4 ;
		RECT 0.000 63.975 27.430 64.455 ;
		LAYER M4 ;
		RECT 0.000 66.175 27.430 66.655 ;
		LAYER M4 ;
		RECT 0.000 68.375 27.430 68.855 ;
		LAYER M4 ;
		RECT 0.000 14.360 27.430 14.840 ;
		LAYER M4 ;
		RECT 0.000 17.660 27.430 18.140 ;
		LAYER M4 ;
		RECT 0.000 16.560 27.430 17.040 ;
		LAYER M4 ;
		RECT 0.000 15.460 27.430 15.940 ;
		LAYER M4 ;
		RECT 0.000 65.075 27.430 65.555 ;
		LAYER M4 ;
		RECT 0.000 6.660 27.430 7.140 ;
		LAYER M4 ;
		RECT 0.000 8.860 27.430 9.340 ;
		LAYER M4 ;
		RECT 0.000 7.760 27.430 8.240 ;
		LAYER M4 ;
		RECT 0.000 13.260 27.430 13.740 ;
		LAYER M4 ;
		RECT 0.000 12.160 27.430 12.640 ;
		LAYER M4 ;
		RECT 0.000 11.060 27.430 11.540 ;
		LAYER M4 ;
		RECT 0.000 9.960 27.430 10.440 ;
		LAYER M3 ;
		RECT 27.280 19.500 27.430 20.805 ;
		LAYER M4 ;
		RECT 0.000 34.600 27.430 34.980 ;
		LAYER M4 ;
		RECT 0.000 21.610 27.430 23.940 ;
		LAYER M4 ;
		RECT 0.000 20.960 27.430 20.990 ;
		LAYER M4 ;
		RECT 0.000 24.700 27.430 25.200 ;
		LAYER M4 ;
		RECT 0.000 25.960 27.430 27.340 ;
		LAYER M4 ;
		RECT 0.000 28.200 27.430 29.250 ;
		LAYER M4 ;
		RECT 0.000 30.740 27.430 32.220 ;
		LAYER M1 ;
		RECT 27.280 59.315 27.430 61.705 ;
		LAYER M4 ;
		RECT 0.000 60.675 27.430 61.155 ;
		LAYER M4 ;
		RECT 0.000 43.910 27.430 46.240 ;
		LAYER M3 ;
		RECT 27.280 13.810 27.430 16.200 ;
		LAYER M3 ;
		RECT 27.280 9.410 27.430 11.800 ;
		LAYER M3 ;
		RECT 27.280 5.010 27.430 7.400 ;
		LAYER M4 ;
		RECT 0.000 69.475 27.430 69.955 ;
		LAYER VIA1 ;
		RECT 0.000 0.000 27.430 71.115 ;
		LAYER M4 ;
		RECT 0.000 3.360 27.430 3.840 ;
		LAYER M2 ;
		RECT 0.000 0.000 27.280 71.115 ;
		LAYER M4 ;
		RECT 0.000 70.575 27.430 71.115 ;
		LAYER M4 ;
		RECT 0.000 0.000 27.430 0.540 ;
		LAYER VIA3 ;
		RECT 0.000 0.000 27.430 71.115 ;
		LAYER VIA2 ;
		RECT 0.000 0.000 27.430 71.115 ;
		LAYER M4 ;
		RECT 0.000 2.260 27.430 2.740 ;
		LAYER M4 ;
		RECT 0.000 4.460 27.430 4.940 ;
		LAYER M4 ;
		RECT 0.000 1.160 27.430 1.640 ;
		LAYER M1 ;
		RECT 0.000 0.000 27.280 71.115 ;
		LAYER M3 ;
		RECT 0.000 0.000 27.280 71.115 ;
		LAYER M4 ;
		RECT 0.000 5.560 27.430 6.040 ;
		LAYER M1 ;
		RECT 27.280 18.210 27.430 18.645 ;
		LAYER M4 ;
		RECT 0.000 19.860 27.430 20.340 ;
		LAYER M4 ;
		RECT 0.000 32.870 27.430 33.250 ;
		LAYER M4 ;
		RECT 0.000 18.760 27.430 19.240 ;
		LAYER M4 ;
		RECT 0.000 48.700 27.430 50.155 ;
		LAYER M4 ;
		RECT 0.000 50.775 27.430 51.255 ;
		LAYER M4 ;
		RECT 0.000 51.875 27.430 52.355 ;
		LAYER M4 ;
		RECT 0.000 46.860 27.430 48.080 ;
		LAYER M4 ;
		RECT 0.000 58.475 27.430 58.955 ;
		LAYER M4 ;
		RECT 0.000 57.375 27.430 57.855 ;
		LAYER M4 ;
		RECT 0.000 56.275 27.430 56.755 ;
		LAYER M4 ;
		RECT 0.000 55.175 27.430 55.655 ;
		LAYER M4 ;
		RECT 0.000 59.575 27.430 60.055 ;
		LAYER M4 ;
		RECT 0.000 54.075 27.430 54.555 ;
		LAYER M4 ;
		RECT 0.000 52.975 27.430 53.455 ;
		LAYER M4 ;
		RECT 0.000 35.630 27.430 37.110 ;
		LAYER M4 ;
		RECT 0.000 38.600 27.430 39.650 ;
		LAYER M4 ;
		RECT 0.000 40.510 27.430 41.890 ;
		LAYER M4 ;
		RECT 0.000 42.650 27.430 43.150 ;
	END
	# End of OBS

END TS6N28HPCPHVTA64X8M4FWBSO

END LIBRARY
